VERSION 5.8 ;
BUSBITCHARS "[]" ;
DIVIDERCHAR "/" ;
UNITS
    DATABASE MICRONS 1000 ;
END UNITS

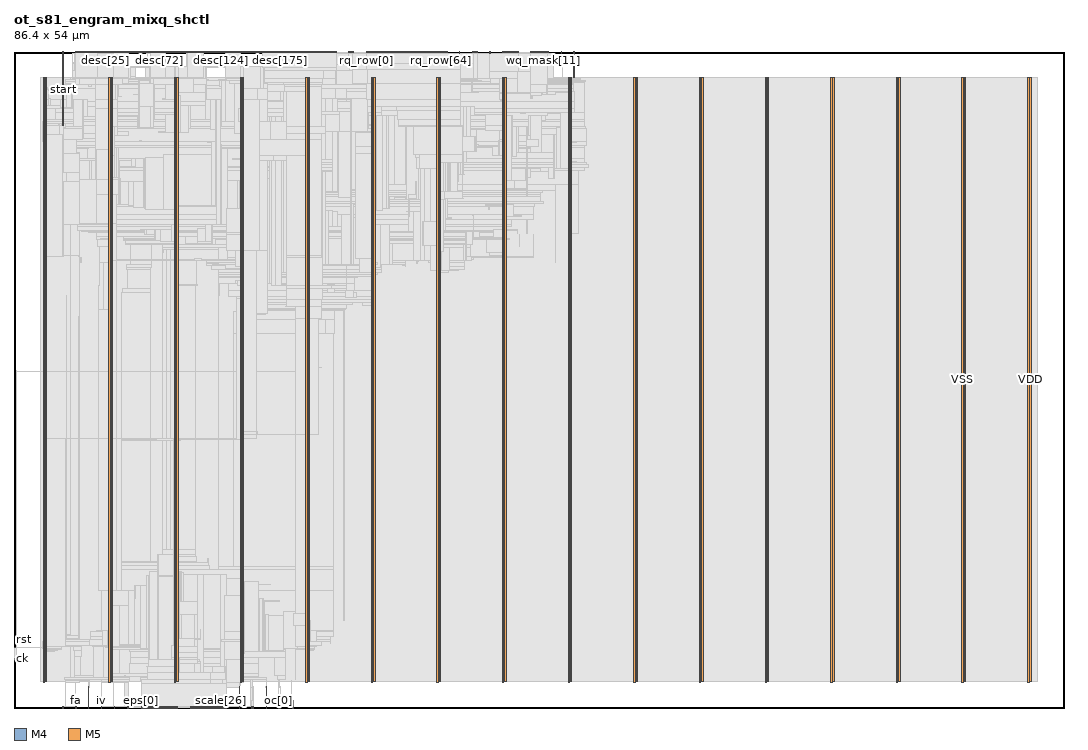
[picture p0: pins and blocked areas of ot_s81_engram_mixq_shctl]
MACRO ot_s81_engram_mixq_shctl
  FOREIGN ot_s81_engram_mixq_shctl 0 0 ;
  CLASS BLOCK ;
  SIZE 86.4 BY 54 ;
  PIN ck
    DIRECTION INPUT ;
    USE SIGNAL ;
    PORT
      LAYER M4 ;
        RECT  0 4.032 0.084 4.056 ;
    END
  END ck
  PIN copy[0]
    DIRECTION OUTPUT ;
    USE SIGNAL ;
    PORT
      LAYER M5 ;
        RECT  9.312 0 9.336 0.084 ;
    END
  END copy[0]
  PIN copy[1]
    DIRECTION OUTPUT ;
    USE SIGNAL ;
    PORT
      LAYER M5 ;
        RECT  9.408 0 9.432 0.084 ;
    END
  END copy[1]
  PIN desc[0]
    DIRECTION INPUT ;
    USE SIGNAL ;
    PORT
      LAYER M5 ;
        RECT  5.088 53.916 5.112 54 ;
    END
  END desc[0]
  PIN desc[100]
    DIRECTION INPUT ;
    USE SIGNAL ;
    PORT
      LAYER M5 ;
        RECT  14.688 53.916 14.712 54 ;
    END
  END desc[100]
  PIN desc[101]
    DIRECTION INPUT ;
    USE SIGNAL ;
    PORT
      LAYER M5 ;
        RECT  14.784 53.916 14.808 54 ;
    END
  END desc[101]
  PIN desc[102]
    DIRECTION INPUT ;
    USE SIGNAL ;
    PORT
      LAYER M5 ;
        RECT  14.88 53.916 14.904 54 ;
    END
  END desc[102]
  PIN desc[103]
    DIRECTION INPUT ;
    USE SIGNAL ;
    PORT
      LAYER M5 ;
        RECT  14.976 53.916 15 54 ;
    END
  END desc[103]
  PIN desc[104]
    DIRECTION INPUT ;
    USE SIGNAL ;
    PORT
      LAYER M5 ;
        RECT  15.072 53.916 15.096 54 ;
    END
  END desc[104]
  PIN desc[105]
    DIRECTION INPUT ;
    USE SIGNAL ;
    PORT
      LAYER M5 ;
        RECT  15.168 53.916 15.192 54 ;
    END
  END desc[105]
  PIN desc[106]
    DIRECTION INPUT ;
    USE SIGNAL ;
    PORT
      LAYER M5 ;
        RECT  15.264 53.916 15.288 54 ;
    END
  END desc[106]
  PIN desc[107]
    DIRECTION INPUT ;
    USE SIGNAL ;
    PORT
      LAYER M5 ;
        RECT  15.36 53.916 15.384 54 ;
    END
  END desc[107]
  PIN desc[108]
    DIRECTION INPUT ;
    USE SIGNAL ;
    PORT
      LAYER M5 ;
        RECT  15.456 53.916 15.48 54 ;
    END
  END desc[108]
  PIN desc[109]
    DIRECTION INPUT ;
    USE SIGNAL ;
    PORT
      LAYER M5 ;
        RECT  15.552 53.916 15.576 54 ;
    END
  END desc[109]
  PIN desc[10]
    DIRECTION INPUT ;
    USE SIGNAL ;
    PORT
      LAYER M5 ;
        RECT  6.048 53.916 6.072 54 ;
    END
  END desc[10]
  PIN desc[110]
    DIRECTION INPUT ;
    USE SIGNAL ;
    PORT
      LAYER M5 ;
        RECT  15.648 53.916 15.672 54 ;
    END
  END desc[110]
  PIN desc[111]
    DIRECTION INPUT ;
    USE SIGNAL ;
    PORT
      LAYER M5 ;
        RECT  15.744 53.916 15.768 54 ;
    END
  END desc[111]
  PIN desc[112]
    DIRECTION INPUT ;
    USE SIGNAL ;
    PORT
      LAYER M5 ;
        RECT  15.84 53.916 15.864 54 ;
    END
  END desc[112]
  PIN desc[113]
    DIRECTION INPUT ;
    USE SIGNAL ;
    PORT
      LAYER M5 ;
        RECT  15.936 53.916 15.96 54 ;
    END
  END desc[113]
  PIN desc[114]
    DIRECTION INPUT ;
    USE SIGNAL ;
    PORT
      LAYER M5 ;
        RECT  16.032 53.916 16.056 54 ;
    END
  END desc[114]
  PIN desc[115]
    DIRECTION INPUT ;
    USE SIGNAL ;
    PORT
      LAYER M5 ;
        RECT  16.128 53.916 16.152 54 ;
    END
  END desc[115]
  PIN desc[116]
    DIRECTION INPUT ;
    USE SIGNAL ;
    PORT
      LAYER M5 ;
        RECT  16.224 53.916 16.248 54 ;
    END
  END desc[116]
  PIN desc[117]
    DIRECTION INPUT ;
    USE SIGNAL ;
    PORT
      LAYER M5 ;
        RECT  16.32 53.916 16.344 54 ;
    END
  END desc[117]
  PIN desc[118]
    DIRECTION INPUT ;
    USE SIGNAL ;
    PORT
      LAYER M5 ;
        RECT  16.416 53.916 16.44 54 ;
    END
  END desc[118]
  PIN desc[119]
    DIRECTION INPUT ;
    USE SIGNAL ;
    PORT
      LAYER M5 ;
        RECT  16.512 53.916 16.536 54 ;
    END
  END desc[119]
  PIN desc[11]
    DIRECTION INPUT ;
    USE SIGNAL ;
    PORT
      LAYER M5 ;
        RECT  6.144 53.916 6.168 54 ;
    END
  END desc[11]
  PIN desc[120]
    DIRECTION INPUT ;
    USE SIGNAL ;
    PORT
      LAYER M5 ;
        RECT  16.608 53.916 16.632 54 ;
    END
  END desc[120]
  PIN desc[121]
    DIRECTION INPUT ;
    USE SIGNAL ;
    PORT
      LAYER M5 ;
        RECT  16.704 53.916 16.728 54 ;
    END
  END desc[121]
  PIN desc[122]
    DIRECTION INPUT ;
    USE SIGNAL ;
    PORT
      LAYER M5 ;
        RECT  16.8 53.916 16.824 54 ;
    END
  END desc[122]
  PIN desc[123]
    DIRECTION INPUT ;
    USE SIGNAL ;
    PORT
      LAYER M5 ;
        RECT  16.896 53.916 16.92 54 ;
    END
  END desc[123]
  PIN desc[124]
    DIRECTION INPUT ;
    USE SIGNAL ;
    PORT
      LAYER M5 ;
        RECT  16.992 53.916 17.016 54 ;
    END
  END desc[124]
  PIN desc[125]
    DIRECTION INPUT ;
    USE SIGNAL ;
    PORT
      LAYER M5 ;
        RECT  17.088 53.916 17.112 54 ;
    END
  END desc[125]
  PIN desc[126]
    DIRECTION INPUT ;
    USE SIGNAL ;
    PORT
      LAYER M5 ;
        RECT  17.184 53.916 17.208 54 ;
    END
  END desc[126]
  PIN desc[127]
    DIRECTION INPUT ;
    USE SIGNAL ;
    PORT
      LAYER M5 ;
        RECT  17.28 53.916 17.304 54 ;
    END
  END desc[127]
  PIN desc[128]
    DIRECTION INPUT ;
    USE SIGNAL ;
    PORT
      LAYER M5 ;
        RECT  17.376 53.916 17.4 54 ;
    END
  END desc[128]
  PIN desc[129]
    DIRECTION INPUT ;
    USE SIGNAL ;
    PORT
      LAYER M5 ;
        RECT  17.472 53.916 17.496 54 ;
    END
  END desc[129]
  PIN desc[12]
    DIRECTION INPUT ;
    USE SIGNAL ;
    PORT
      LAYER M5 ;
        RECT  6.24 53.916 6.264 54 ;
    END
  END desc[12]
  PIN desc[130]
    DIRECTION INPUT ;
    USE SIGNAL ;
    PORT
      LAYER M5 ;
        RECT  17.568 53.916 17.592 54 ;
    END
  END desc[130]
  PIN desc[131]
    DIRECTION INPUT ;
    USE SIGNAL ;
    PORT
      LAYER M5 ;
        RECT  17.664 53.916 17.688 54 ;
    END
  END desc[131]
  PIN desc[132]
    DIRECTION INPUT ;
    USE SIGNAL ;
    PORT
      LAYER M5 ;
        RECT  17.76 53.916 17.784 54 ;
    END
  END desc[132]
  PIN desc[133]
    DIRECTION INPUT ;
    USE SIGNAL ;
    PORT
      LAYER M5 ;
        RECT  17.856 53.916 17.88 54 ;
    END
  END desc[133]
  PIN desc[134]
    DIRECTION INPUT ;
    USE SIGNAL ;
    PORT
      LAYER M5 ;
        RECT  17.952 53.916 17.976 54 ;
    END
  END desc[134]
  PIN desc[135]
    DIRECTION INPUT ;
    USE SIGNAL ;
    PORT
      LAYER M5 ;
        RECT  18.048 53.916 18.072 54 ;
    END
  END desc[135]
  PIN desc[136]
    DIRECTION INPUT ;
    USE SIGNAL ;
    PORT
      LAYER M5 ;
        RECT  18.144 53.916 18.168 54 ;
    END
  END desc[136]
  PIN desc[137]
    DIRECTION INPUT ;
    USE SIGNAL ;
    PORT
      LAYER M5 ;
        RECT  18.24 53.916 18.264 54 ;
    END
  END desc[137]
  PIN desc[138]
    DIRECTION INPUT ;
    USE SIGNAL ;
    PORT
      LAYER M5 ;
        RECT  18.336 53.916 18.36 54 ;
    END
  END desc[138]
  PIN desc[139]
    DIRECTION INPUT ;
    USE SIGNAL ;
    PORT
      LAYER M5 ;
        RECT  18.432 53.916 18.456 54 ;
    END
  END desc[139]
  PIN desc[13]
    DIRECTION INPUT ;
    USE SIGNAL ;
    PORT
      LAYER M5 ;
        RECT  6.336 53.916 6.36 54 ;
    END
  END desc[13]
  PIN desc[140]
    DIRECTION INPUT ;
    USE SIGNAL ;
    PORT
      LAYER M5 ;
        RECT  18.528 53.916 18.552 54 ;
    END
  END desc[140]
  PIN desc[141]
    DIRECTION INPUT ;
    USE SIGNAL ;
    PORT
      LAYER M5 ;
        RECT  18.624 53.916 18.648 54 ;
    END
  END desc[141]
  PIN desc[142]
    DIRECTION INPUT ;
    USE SIGNAL ;
    PORT
      LAYER M5 ;
        RECT  18.72 53.916 18.744 54 ;
    END
  END desc[142]
  PIN desc[143]
    DIRECTION INPUT ;
    USE SIGNAL ;
    PORT
      LAYER M5 ;
        RECT  18.816 53.916 18.84 54 ;
    END
  END desc[143]
  PIN desc[144]
    DIRECTION INPUT ;
    USE SIGNAL ;
    PORT
      LAYER M5 ;
        RECT  18.912 53.916 18.936 54 ;
    END
  END desc[144]
  PIN desc[145]
    DIRECTION INPUT ;
    USE SIGNAL ;
    PORT
      LAYER M5 ;
        RECT  19.008 53.916 19.032 54 ;
    END
  END desc[145]
  PIN desc[146]
    DIRECTION INPUT ;
    USE SIGNAL ;
    PORT
      LAYER M5 ;
        RECT  19.104 53.916 19.128 54 ;
    END
  END desc[146]
  PIN desc[147]
    DIRECTION INPUT ;
    USE SIGNAL ;
    PORT
      LAYER M5 ;
        RECT  19.2 53.916 19.224 54 ;
    END
  END desc[147]
  PIN desc[148]
    DIRECTION INPUT ;
    USE SIGNAL ;
    PORT
      LAYER M5 ;
        RECT  19.296 53.916 19.32 54 ;
    END
  END desc[148]
  PIN desc[149]
    DIRECTION INPUT ;
    USE SIGNAL ;
    PORT
      LAYER M5 ;
        RECT  19.392 53.916 19.416 54 ;
    END
  END desc[149]
  PIN desc[14]
    DIRECTION INPUT ;
    USE SIGNAL ;
    PORT
      LAYER M5 ;
        RECT  6.432 53.916 6.456 54 ;
    END
  END desc[14]
  PIN desc[150]
    DIRECTION INPUT ;
    USE SIGNAL ;
    PORT
      LAYER M5 ;
        RECT  19.488 53.916 19.512 54 ;
    END
  END desc[150]
  PIN desc[151]
    DIRECTION INPUT ;
    USE SIGNAL ;
    PORT
      LAYER M5 ;
        RECT  19.584 53.916 19.608 54 ;
    END
  END desc[151]
  PIN desc[152]
    DIRECTION INPUT ;
    USE SIGNAL ;
    PORT
      LAYER M5 ;
        RECT  19.68 53.916 19.704 54 ;
    END
  END desc[152]
  PIN desc[153]
    DIRECTION INPUT ;
    USE SIGNAL ;
    PORT
      LAYER M5 ;
        RECT  19.776 53.916 19.8 54 ;
    END
  END desc[153]
  PIN desc[154]
    DIRECTION INPUT ;
    USE SIGNAL ;
    PORT
      LAYER M5 ;
        RECT  19.872 53.916 19.896 54 ;
    END
  END desc[154]
  PIN desc[155]
    DIRECTION INPUT ;
    USE SIGNAL ;
    PORT
      LAYER M5 ;
        RECT  19.968 53.916 19.992 54 ;
    END
  END desc[155]
  PIN desc[156]
    DIRECTION INPUT ;
    USE SIGNAL ;
    PORT
      LAYER M5 ;
        RECT  20.064 53.916 20.088 54 ;
    END
  END desc[156]
  PIN desc[157]
    DIRECTION INPUT ;
    USE SIGNAL ;
    PORT
      LAYER M5 ;
        RECT  20.16 53.916 20.184 54 ;
    END
  END desc[157]
  PIN desc[158]
    DIRECTION INPUT ;
    USE SIGNAL ;
    PORT
      LAYER M5 ;
        RECT  20.256 53.916 20.28 54 ;
    END
  END desc[158]
  PIN desc[159]
    DIRECTION INPUT ;
    USE SIGNAL ;
    PORT
      LAYER M5 ;
        RECT  20.352 53.916 20.376 54 ;
    END
  END desc[159]
  PIN desc[15]
    DIRECTION INPUT ;
    USE SIGNAL ;
    PORT
      LAYER M5 ;
        RECT  6.528 53.916 6.552 54 ;
    END
  END desc[15]
  PIN desc[160]
    DIRECTION INPUT ;
    USE SIGNAL ;
    PORT
      LAYER M5 ;
        RECT  20.448 53.916 20.472 54 ;
    END
  END desc[160]
  PIN desc[161]
    DIRECTION INPUT ;
    USE SIGNAL ;
    PORT
      LAYER M5 ;
        RECT  20.544 53.916 20.568 54 ;
    END
  END desc[161]
  PIN desc[162]
    DIRECTION INPUT ;
    USE SIGNAL ;
    PORT
      LAYER M5 ;
        RECT  20.64 53.916 20.664 54 ;
    END
  END desc[162]
  PIN desc[163]
    DIRECTION INPUT ;
    USE SIGNAL ;
    PORT
      LAYER M5 ;
        RECT  20.736 53.916 20.76 54 ;
    END
  END desc[163]
  PIN desc[164]
    DIRECTION INPUT ;
    USE SIGNAL ;
    PORT
      LAYER M5 ;
        RECT  20.832 53.916 20.856 54 ;
    END
  END desc[164]
  PIN desc[165]
    DIRECTION INPUT ;
    USE SIGNAL ;
    PORT
      LAYER M5 ;
        RECT  20.928 53.916 20.952 54 ;
    END
  END desc[165]
  PIN desc[166]
    DIRECTION INPUT ;
    USE SIGNAL ;
    PORT
      LAYER M5 ;
        RECT  21.024 53.916 21.048 54 ;
    END
  END desc[166]
  PIN desc[167]
    DIRECTION INPUT ;
    USE SIGNAL ;
    PORT
      LAYER M5 ;
        RECT  21.12 53.916 21.144 54 ;
    END
  END desc[167]
  PIN desc[168]
    DIRECTION INPUT ;
    USE SIGNAL ;
    PORT
      LAYER M5 ;
        RECT  21.216 53.916 21.24 54 ;
    END
  END desc[168]
  PIN desc[169]
    DIRECTION INPUT ;
    USE SIGNAL ;
    PORT
      LAYER M5 ;
        RECT  21.312 53.916 21.336 54 ;
    END
  END desc[169]
  PIN desc[16]
    DIRECTION INPUT ;
    USE SIGNAL ;
    PORT
      LAYER M5 ;
        RECT  6.624 53.916 6.648 54 ;
    END
  END desc[16]
  PIN desc[170]
    DIRECTION INPUT ;
    USE SIGNAL ;
    PORT
      LAYER M5 ;
        RECT  21.408 53.916 21.432 54 ;
    END
  END desc[170]
  PIN desc[171]
    DIRECTION INPUT ;
    USE SIGNAL ;
    PORT
      LAYER M5 ;
        RECT  21.504 53.916 21.528 54 ;
    END
  END desc[171]
  PIN desc[172]
    DIRECTION INPUT ;
    USE SIGNAL ;
    PORT
      LAYER M5 ;
        RECT  21.6 53.916 21.624 54 ;
    END
  END desc[172]
  PIN desc[173]
    DIRECTION INPUT ;
    USE SIGNAL ;
    PORT
      LAYER M5 ;
        RECT  21.696 53.916 21.72 54 ;
    END
  END desc[173]
  PIN desc[174]
    DIRECTION INPUT ;
    USE SIGNAL ;
    PORT
      LAYER M5 ;
        RECT  21.792 53.916 21.816 54 ;
    END
  END desc[174]
  PIN desc[175]
    DIRECTION INPUT ;
    USE SIGNAL ;
    PORT
      LAYER M5 ;
        RECT  21.888 53.916 21.912 54 ;
    END
  END desc[175]
  PIN desc[176]
    DIRECTION INPUT ;
    USE SIGNAL ;
    PORT
      LAYER M5 ;
        RECT  21.984 53.916 22.008 54 ;
    END
  END desc[176]
  PIN desc[177]
    DIRECTION INPUT ;
    USE SIGNAL ;
    PORT
      LAYER M5 ;
        RECT  22.08 53.916 22.104 54 ;
    END
  END desc[177]
  PIN desc[178]
    DIRECTION INPUT ;
    USE SIGNAL ;
    PORT
      LAYER M5 ;
        RECT  22.176 53.916 22.2 54 ;
    END
  END desc[178]
  PIN desc[179]
    DIRECTION INPUT ;
    USE SIGNAL ;
    PORT
      LAYER M5 ;
        RECT  22.272 53.916 22.296 54 ;
    END
  END desc[179]
  PIN desc[17]
    DIRECTION INPUT ;
    USE SIGNAL ;
    PORT
      LAYER M5 ;
        RECT  6.72 53.916 6.744 54 ;
    END
  END desc[17]
  PIN desc[180]
    DIRECTION INPUT ;
    USE SIGNAL ;
    PORT
      LAYER M5 ;
        RECT  22.368 53.916 22.392 54 ;
    END
  END desc[180]
  PIN desc[181]
    DIRECTION INPUT ;
    USE SIGNAL ;
    PORT
      LAYER M5 ;
        RECT  22.464 53.916 22.488 54 ;
    END
  END desc[181]
  PIN desc[182]
    DIRECTION INPUT ;
    USE SIGNAL ;
    PORT
      LAYER M5 ;
        RECT  22.56 53.916 22.584 54 ;
    END
  END desc[182]
  PIN desc[183]
    DIRECTION INPUT ;
    USE SIGNAL ;
    PORT
      LAYER M5 ;
        RECT  22.656 53.916 22.68 54 ;
    END
  END desc[183]
  PIN desc[184]
    DIRECTION INPUT ;
    USE SIGNAL ;
    PORT
      LAYER M5 ;
        RECT  22.752 53.916 22.776 54 ;
    END
  END desc[184]
  PIN desc[185]
    DIRECTION INPUT ;
    USE SIGNAL ;
    PORT
      LAYER M5 ;
        RECT  22.848 53.916 22.872 54 ;
    END
  END desc[185]
  PIN desc[186]
    DIRECTION INPUT ;
    USE SIGNAL ;
    PORT
      LAYER M5 ;
        RECT  22.944 53.916 22.968 54 ;
    END
  END desc[186]
  PIN desc[187]
    DIRECTION INPUT ;
    USE SIGNAL ;
    PORT
      LAYER M5 ;
        RECT  23.04 53.916 23.064 54 ;
    END
  END desc[187]
  PIN desc[188]
    DIRECTION INPUT ;
    USE SIGNAL ;
    PORT
      LAYER M5 ;
        RECT  23.136 53.916 23.16 54 ;
    END
  END desc[188]
  PIN desc[189]
    DIRECTION INPUT ;
    USE SIGNAL ;
    PORT
      LAYER M5 ;
        RECT  23.232 53.916 23.256 54 ;
    END
  END desc[189]
  PIN desc[18]
    DIRECTION INPUT ;
    USE SIGNAL ;
    PORT
      LAYER M5 ;
        RECT  6.816 53.916 6.84 54 ;
    END
  END desc[18]
  PIN desc[190]
    DIRECTION INPUT ;
    USE SIGNAL ;
    PORT
      LAYER M5 ;
        RECT  23.328 53.916 23.352 54 ;
    END
  END desc[190]
  PIN desc[191]
    DIRECTION INPUT ;
    USE SIGNAL ;
    PORT
      LAYER M5 ;
        RECT  23.424 53.916 23.448 54 ;
    END
  END desc[191]
  PIN desc[192]
    DIRECTION INPUT ;
    USE SIGNAL ;
    PORT
      LAYER M5 ;
        RECT  23.52 53.916 23.544 54 ;
    END
  END desc[192]
  PIN desc[193]
    DIRECTION INPUT ;
    USE SIGNAL ;
    PORT
      LAYER M5 ;
        RECT  23.616 53.916 23.64 54 ;
    END
  END desc[193]
  PIN desc[194]
    DIRECTION INPUT ;
    USE SIGNAL ;
    PORT
      LAYER M5 ;
        RECT  23.712 53.916 23.736 54 ;
    END
  END desc[194]
  PIN desc[195]
    DIRECTION INPUT ;
    USE SIGNAL ;
    PORT
      LAYER M5 ;
        RECT  23.808 53.916 23.832 54 ;
    END
  END desc[195]
  PIN desc[196]
    DIRECTION INPUT ;
    USE SIGNAL ;
    PORT
      LAYER M5 ;
        RECT  23.904 53.916 23.928 54 ;
    END
  END desc[196]
  PIN desc[197]
    DIRECTION INPUT ;
    USE SIGNAL ;
    PORT
      LAYER M5 ;
        RECT  24 53.916 24.024 54 ;
    END
  END desc[197]
  PIN desc[198]
    DIRECTION INPUT ;
    USE SIGNAL ;
    PORT
      LAYER M5 ;
        RECT  24.096 53.916 24.12 54 ;
    END
  END desc[198]
  PIN desc[199]
    DIRECTION INPUT ;
    USE SIGNAL ;
    PORT
      LAYER M5 ;
        RECT  24.192 53.916 24.216 54 ;
    END
  END desc[199]
  PIN desc[19]
    DIRECTION INPUT ;
    USE SIGNAL ;
    PORT
      LAYER M5 ;
        RECT  6.912 53.916 6.936 54 ;
    END
  END desc[19]
  PIN desc[1]
    DIRECTION INPUT ;
    USE SIGNAL ;
    PORT
      LAYER M5 ;
        RECT  5.184 53.916 5.208 54 ;
    END
  END desc[1]
  PIN desc[200]
    DIRECTION INPUT ;
    USE SIGNAL ;
    PORT
      LAYER M5 ;
        RECT  24.288 53.916 24.312 54 ;
    END
  END desc[200]
  PIN desc[201]
    DIRECTION INPUT ;
    USE SIGNAL ;
    PORT
      LAYER M5 ;
        RECT  24.384 53.916 24.408 54 ;
    END
  END desc[201]
  PIN desc[202]
    DIRECTION INPUT ;
    USE SIGNAL ;
    PORT
      LAYER M5 ;
        RECT  24.48 53.916 24.504 54 ;
    END
  END desc[202]
  PIN desc[203]
    DIRECTION INPUT ;
    USE SIGNAL ;
    PORT
      LAYER M5 ;
        RECT  24.576 53.916 24.6 54 ;
    END
  END desc[203]
  PIN desc[204]
    DIRECTION INPUT ;
    USE SIGNAL ;
    PORT
      LAYER M5 ;
        RECT  24.672 53.916 24.696 54 ;
    END
  END desc[204]
  PIN desc[205]
    DIRECTION INPUT ;
    USE SIGNAL ;
    PORT
      LAYER M5 ;
        RECT  24.768 53.916 24.792 54 ;
    END
  END desc[205]
  PIN desc[206]
    DIRECTION INPUT ;
    USE SIGNAL ;
    PORT
      LAYER M5 ;
        RECT  24.864 53.916 24.888 54 ;
    END
  END desc[206]
  PIN desc[207]
    DIRECTION INPUT ;
    USE SIGNAL ;
    PORT
      LAYER M5 ;
        RECT  24.96 53.916 24.984 54 ;
    END
  END desc[207]
  PIN desc[208]
    DIRECTION INPUT ;
    USE SIGNAL ;
    PORT
      LAYER M5 ;
        RECT  25.056 53.916 25.08 54 ;
    END
  END desc[208]
  PIN desc[209]
    DIRECTION INPUT ;
    USE SIGNAL ;
    PORT
      LAYER M5 ;
        RECT  25.152 53.916 25.176 54 ;
    END
  END desc[209]
  PIN desc[20]
    DIRECTION INPUT ;
    USE SIGNAL ;
    PORT
      LAYER M5 ;
        RECT  7.008 53.916 7.032 54 ;
    END
  END desc[20]
  PIN desc[210]
    DIRECTION INPUT ;
    USE SIGNAL ;
    PORT
      LAYER M5 ;
        RECT  25.248 53.916 25.272 54 ;
    END
  END desc[210]
  PIN desc[211]
    DIRECTION INPUT ;
    USE SIGNAL ;
    PORT
      LAYER M5 ;
        RECT  25.344 53.916 25.368 54 ;
    END
  END desc[211]
  PIN desc[212]
    DIRECTION INPUT ;
    USE SIGNAL ;
    PORT
      LAYER M5 ;
        RECT  25.44 53.916 25.464 54 ;
    END
  END desc[212]
  PIN desc[213]
    DIRECTION INPUT ;
    USE SIGNAL ;
    PORT
      LAYER M5 ;
        RECT  25.536 53.916 25.56 54 ;
    END
  END desc[213]
  PIN desc[214]
    DIRECTION INPUT ;
    USE SIGNAL ;
    PORT
      LAYER M5 ;
        RECT  25.632 53.916 25.656 54 ;
    END
  END desc[214]
  PIN desc[215]
    DIRECTION INPUT ;
    USE SIGNAL ;
    PORT
      LAYER M5 ;
        RECT  25.728 53.916 25.752 54 ;
    END
  END desc[215]
  PIN desc[216]
    DIRECTION INPUT ;
    USE SIGNAL ;
    PORT
      LAYER M5 ;
        RECT  25.824 53.916 25.848 54 ;
    END
  END desc[216]
  PIN desc[217]
    DIRECTION INPUT ;
    USE SIGNAL ;
    PORT
      LAYER M5 ;
        RECT  25.92 53.916 25.944 54 ;
    END
  END desc[217]
  PIN desc[218]
    DIRECTION INPUT ;
    USE SIGNAL ;
    PORT
      LAYER M5 ;
        RECT  26.016 53.916 26.04 54 ;
    END
  END desc[218]
  PIN desc[219]
    DIRECTION INPUT ;
    USE SIGNAL ;
    PORT
      LAYER M5 ;
        RECT  26.112 53.916 26.136 54 ;
    END
  END desc[219]
  PIN desc[21]
    DIRECTION INPUT ;
    USE SIGNAL ;
    PORT
      LAYER M5 ;
        RECT  7.104 53.916 7.128 54 ;
    END
  END desc[21]
  PIN desc[220]
    DIRECTION INPUT ;
    USE SIGNAL ;
    PORT
      LAYER M5 ;
        RECT  26.208 53.916 26.232 54 ;
    END
  END desc[220]
  PIN desc[221]
    DIRECTION INPUT ;
    USE SIGNAL ;
    PORT
      LAYER M5 ;
        RECT  26.304 53.916 26.328 54 ;
    END
  END desc[221]
  PIN desc[222]
    DIRECTION INPUT ;
    USE SIGNAL ;
    PORT
      LAYER M5 ;
        RECT  26.4 53.916 26.424 54 ;
    END
  END desc[222]
  PIN desc[223]
    DIRECTION INPUT ;
    USE SIGNAL ;
    PORT
      LAYER M5 ;
        RECT  26.496 53.916 26.52 54 ;
    END
  END desc[223]
  PIN desc[22]
    DIRECTION INPUT ;
    USE SIGNAL ;
    PORT
      LAYER M5 ;
        RECT  7.2 53.916 7.224 54 ;
    END
  END desc[22]
  PIN desc[23]
    DIRECTION INPUT ;
    USE SIGNAL ;
    PORT
      LAYER M5 ;
        RECT  7.296 53.916 7.32 54 ;
    END
  END desc[23]
  PIN desc[24]
    DIRECTION INPUT ;
    USE SIGNAL ;
    PORT
      LAYER M5 ;
        RECT  7.392 53.916 7.416 54 ;
    END
  END desc[24]
  PIN desc[25]
    DIRECTION INPUT ;
    USE SIGNAL ;
    PORT
      LAYER M5 ;
        RECT  7.488 53.916 7.512 54 ;
    END
  END desc[25]
  PIN desc[26]
    DIRECTION INPUT ;
    USE SIGNAL ;
    PORT
      LAYER M5 ;
        RECT  7.584 53.916 7.608 54 ;
    END
  END desc[26]
  PIN desc[27]
    DIRECTION INPUT ;
    USE SIGNAL ;
    PORT
      LAYER M5 ;
        RECT  7.68 53.916 7.704 54 ;
    END
  END desc[27]
  PIN desc[28]
    DIRECTION INPUT ;
    USE SIGNAL ;
    PORT
      LAYER M5 ;
        RECT  7.776 53.916 7.8 54 ;
    END
  END desc[28]
  PIN desc[29]
    DIRECTION INPUT ;
    USE SIGNAL ;
    PORT
      LAYER M5 ;
        RECT  7.872 53.916 7.896 54 ;
    END
  END desc[29]
  PIN desc[2]
    DIRECTION INPUT ;
    USE SIGNAL ;
    PORT
      LAYER M5 ;
        RECT  5.28 53.916 5.304 54 ;
    END
  END desc[2]
  PIN desc[30]
    DIRECTION INPUT ;
    USE SIGNAL ;
    PORT
      LAYER M5 ;
        RECT  7.968 53.916 7.992 54 ;
    END
  END desc[30]
  PIN desc[31]
    DIRECTION INPUT ;
    USE SIGNAL ;
    PORT
      LAYER M5 ;
        RECT  8.064 53.916 8.088 54 ;
    END
  END desc[31]
  PIN desc[32]
    DIRECTION INPUT ;
    USE SIGNAL ;
    PORT
      LAYER M5 ;
        RECT  8.16 53.916 8.184 54 ;
    END
  END desc[32]
  PIN desc[33]
    DIRECTION INPUT ;
    USE SIGNAL ;
    PORT
      LAYER M5 ;
        RECT  8.256 53.916 8.28 54 ;
    END
  END desc[33]
  PIN desc[34]
    DIRECTION INPUT ;
    USE SIGNAL ;
    PORT
      LAYER M5 ;
        RECT  8.352 53.916 8.376 54 ;
    END
  END desc[34]
  PIN desc[35]
    DIRECTION INPUT ;
    USE SIGNAL ;
    PORT
      LAYER M5 ;
        RECT  8.448 53.916 8.472 54 ;
    END
  END desc[35]
  PIN desc[36]
    DIRECTION INPUT ;
    USE SIGNAL ;
    PORT
      LAYER M5 ;
        RECT  8.544 53.916 8.568 54 ;
    END
  END desc[36]
  PIN desc[37]
    DIRECTION INPUT ;
    USE SIGNAL ;
    PORT
      LAYER M5 ;
        RECT  8.64 53.916 8.664 54 ;
    END
  END desc[37]
  PIN desc[38]
    DIRECTION INPUT ;
    USE SIGNAL ;
    PORT
      LAYER M5 ;
        RECT  8.736 53.916 8.76 54 ;
    END
  END desc[38]
  PIN desc[39]
    DIRECTION INPUT ;
    USE SIGNAL ;
    PORT
      LAYER M5 ;
        RECT  8.832 53.916 8.856 54 ;
    END
  END desc[39]
  PIN desc[3]
    DIRECTION INPUT ;
    USE SIGNAL ;
    PORT
      LAYER M5 ;
        RECT  5.376 53.916 5.4 54 ;
    END
  END desc[3]
  PIN desc[40]
    DIRECTION INPUT ;
    USE SIGNAL ;
    PORT
      LAYER M5 ;
        RECT  8.928 53.916 8.952 54 ;
    END
  END desc[40]
  PIN desc[41]
    DIRECTION INPUT ;
    USE SIGNAL ;
    PORT
      LAYER M5 ;
        RECT  9.024 53.916 9.048 54 ;
    END
  END desc[41]
  PIN desc[42]
    DIRECTION INPUT ;
    USE SIGNAL ;
    PORT
      LAYER M5 ;
        RECT  9.12 53.916 9.144 54 ;
    END
  END desc[42]
  PIN desc[43]
    DIRECTION INPUT ;
    USE SIGNAL ;
    PORT
      LAYER M5 ;
        RECT  9.216 53.916 9.24 54 ;
    END
  END desc[43]
  PIN desc[44]
    DIRECTION INPUT ;
    USE SIGNAL ;
    PORT
      LAYER M5 ;
        RECT  9.312 53.916 9.336 54 ;
    END
  END desc[44]
  PIN desc[45]
    DIRECTION INPUT ;
    USE SIGNAL ;
    PORT
      LAYER M5 ;
        RECT  9.408 53.916 9.432 54 ;
    END
  END desc[45]
  PIN desc[46]
    DIRECTION INPUT ;
    USE SIGNAL ;
    PORT
      LAYER M5 ;
        RECT  9.504 53.916 9.528 54 ;
    END
  END desc[46]
  PIN desc[47]
    DIRECTION INPUT ;
    USE SIGNAL ;
    PORT
      LAYER M5 ;
        RECT  9.6 53.916 9.624 54 ;
    END
  END desc[47]
  PIN desc[48]
    DIRECTION INPUT ;
    USE SIGNAL ;
    PORT
      LAYER M5 ;
        RECT  9.696 53.916 9.72 54 ;
    END
  END desc[48]
  PIN desc[49]
    DIRECTION INPUT ;
    USE SIGNAL ;
    PORT
      LAYER M5 ;
        RECT  9.792 53.916 9.816 54 ;
    END
  END desc[49]
  PIN desc[4]
    DIRECTION INPUT ;
    USE SIGNAL ;
    PORT
      LAYER M5 ;
        RECT  5.472 53.916 5.496 54 ;
    END
  END desc[4]
  PIN desc[50]
    DIRECTION INPUT ;
    USE SIGNAL ;
    PORT
      LAYER M5 ;
        RECT  9.888 53.916 9.912 54 ;
    END
  END desc[50]
  PIN desc[51]
    DIRECTION INPUT ;
    USE SIGNAL ;
    PORT
      LAYER M5 ;
        RECT  9.984 53.916 10.008 54 ;
    END
  END desc[51]
  PIN desc[52]
    DIRECTION INPUT ;
    USE SIGNAL ;
    PORT
      LAYER M5 ;
        RECT  10.08 53.916 10.104 54 ;
    END
  END desc[52]
  PIN desc[53]
    DIRECTION INPUT ;
    USE SIGNAL ;
    PORT
      LAYER M5 ;
        RECT  10.176 53.916 10.2 54 ;
    END
  END desc[53]
  PIN desc[54]
    DIRECTION INPUT ;
    USE SIGNAL ;
    PORT
      LAYER M5 ;
        RECT  10.272 53.916 10.296 54 ;
    END
  END desc[54]
  PIN desc[55]
    DIRECTION INPUT ;
    USE SIGNAL ;
    PORT
      LAYER M5 ;
        RECT  10.368 53.916 10.392 54 ;
    END
  END desc[55]
  PIN desc[56]
    DIRECTION INPUT ;
    USE SIGNAL ;
    PORT
      LAYER M5 ;
        RECT  10.464 53.916 10.488 54 ;
    END
  END desc[56]
  PIN desc[57]
    DIRECTION INPUT ;
    USE SIGNAL ;
    PORT
      LAYER M5 ;
        RECT  10.56 53.916 10.584 54 ;
    END
  END desc[57]
  PIN desc[58]
    DIRECTION INPUT ;
    USE SIGNAL ;
    PORT
      LAYER M5 ;
        RECT  10.656 53.916 10.68 54 ;
    END
  END desc[58]
  PIN desc[59]
    DIRECTION INPUT ;
    USE SIGNAL ;
    PORT
      LAYER M5 ;
        RECT  10.752 53.916 10.776 54 ;
    END
  END desc[59]
  PIN desc[5]
    DIRECTION INPUT ;
    USE SIGNAL ;
    PORT
      LAYER M5 ;
        RECT  5.568 53.916 5.592 54 ;
    END
  END desc[5]
  PIN desc[60]
    DIRECTION INPUT ;
    USE SIGNAL ;
    PORT
      LAYER M5 ;
        RECT  10.848 53.916 10.872 54 ;
    END
  END desc[60]
  PIN desc[61]
    DIRECTION INPUT ;
    USE SIGNAL ;
    PORT
      LAYER M5 ;
        RECT  10.944 53.916 10.968 54 ;
    END
  END desc[61]
  PIN desc[62]
    DIRECTION INPUT ;
    USE SIGNAL ;
    PORT
      LAYER M5 ;
        RECT  11.04 53.916 11.064 54 ;
    END
  END desc[62]
  PIN desc[63]
    DIRECTION INPUT ;
    USE SIGNAL ;
    PORT
      LAYER M5 ;
        RECT  11.136 53.916 11.16 54 ;
    END
  END desc[63]
  PIN desc[64]
    DIRECTION INPUT ;
    USE SIGNAL ;
    PORT
      LAYER M5 ;
        RECT  11.232 53.916 11.256 54 ;
    END
  END desc[64]
  PIN desc[65]
    DIRECTION INPUT ;
    USE SIGNAL ;
    PORT
      LAYER M5 ;
        RECT  11.328 53.916 11.352 54 ;
    END
  END desc[65]
  PIN desc[66]
    DIRECTION INPUT ;
    USE SIGNAL ;
    PORT
      LAYER M5 ;
        RECT  11.424 53.916 11.448 54 ;
    END
  END desc[66]
  PIN desc[67]
    DIRECTION INPUT ;
    USE SIGNAL ;
    PORT
      LAYER M5 ;
        RECT  11.52 53.916 11.544 54 ;
    END
  END desc[67]
  PIN desc[68]
    DIRECTION INPUT ;
    USE SIGNAL ;
    PORT
      LAYER M5 ;
        RECT  11.616 53.916 11.64 54 ;
    END
  END desc[68]
  PIN desc[69]
    DIRECTION INPUT ;
    USE SIGNAL ;
    PORT
      LAYER M5 ;
        RECT  11.712 53.916 11.736 54 ;
    END
  END desc[69]
  PIN desc[6]
    DIRECTION INPUT ;
    USE SIGNAL ;
    PORT
      LAYER M5 ;
        RECT  5.664 53.916 5.688 54 ;
    END
  END desc[6]
  PIN desc[70]
    DIRECTION INPUT ;
    USE SIGNAL ;
    PORT
      LAYER M5 ;
        RECT  11.808 53.916 11.832 54 ;
    END
  END desc[70]
  PIN desc[71]
    DIRECTION INPUT ;
    USE SIGNAL ;
    PORT
      LAYER M5 ;
        RECT  11.904 53.916 11.928 54 ;
    END
  END desc[71]
  PIN desc[72]
    DIRECTION INPUT ;
    USE SIGNAL ;
    PORT
      LAYER M5 ;
        RECT  12 53.916 12.024 54 ;
    END
  END desc[72]
  PIN desc[73]
    DIRECTION INPUT ;
    USE SIGNAL ;
    PORT
      LAYER M5 ;
        RECT  12.096 53.916 12.12 54 ;
    END
  END desc[73]
  PIN desc[74]
    DIRECTION INPUT ;
    USE SIGNAL ;
    PORT
      LAYER M5 ;
        RECT  12.192 53.916 12.216 54 ;
    END
  END desc[74]
  PIN desc[75]
    DIRECTION INPUT ;
    USE SIGNAL ;
    PORT
      LAYER M5 ;
        RECT  12.288 53.916 12.312 54 ;
    END
  END desc[75]
  PIN desc[76]
    DIRECTION INPUT ;
    USE SIGNAL ;
    PORT
      LAYER M5 ;
        RECT  12.384 53.916 12.408 54 ;
    END
  END desc[76]
  PIN desc[77]
    DIRECTION INPUT ;
    USE SIGNAL ;
    PORT
      LAYER M5 ;
        RECT  12.48 53.916 12.504 54 ;
    END
  END desc[77]
  PIN desc[78]
    DIRECTION INPUT ;
    USE SIGNAL ;
    PORT
      LAYER M5 ;
        RECT  12.576 53.916 12.6 54 ;
    END
  END desc[78]
  PIN desc[79]
    DIRECTION INPUT ;
    USE SIGNAL ;
    PORT
      LAYER M5 ;
        RECT  12.672 53.916 12.696 54 ;
    END
  END desc[79]
  PIN desc[7]
    DIRECTION INPUT ;
    USE SIGNAL ;
    PORT
      LAYER M5 ;
        RECT  5.76 53.916 5.784 54 ;
    END
  END desc[7]
  PIN desc[80]
    DIRECTION INPUT ;
    USE SIGNAL ;
    PORT
      LAYER M5 ;
        RECT  12.768 53.916 12.792 54 ;
    END
  END desc[80]
  PIN desc[81]
    DIRECTION INPUT ;
    USE SIGNAL ;
    PORT
      LAYER M5 ;
        RECT  12.864 53.916 12.888 54 ;
    END
  END desc[81]
  PIN desc[82]
    DIRECTION INPUT ;
    USE SIGNAL ;
    PORT
      LAYER M5 ;
        RECT  12.96 53.916 12.984 54 ;
    END
  END desc[82]
  PIN desc[83]
    DIRECTION INPUT ;
    USE SIGNAL ;
    PORT
      LAYER M5 ;
        RECT  13.056 53.916 13.08 54 ;
    END
  END desc[83]
  PIN desc[84]
    DIRECTION INPUT ;
    USE SIGNAL ;
    PORT
      LAYER M5 ;
        RECT  13.152 53.916 13.176 54 ;
    END
  END desc[84]
  PIN desc[85]
    DIRECTION INPUT ;
    USE SIGNAL ;
    PORT
      LAYER M5 ;
        RECT  13.248 53.916 13.272 54 ;
    END
  END desc[85]
  PIN desc[86]
    DIRECTION INPUT ;
    USE SIGNAL ;
    PORT
      LAYER M5 ;
        RECT  13.344 53.916 13.368 54 ;
    END
  END desc[86]
  PIN desc[87]
    DIRECTION INPUT ;
    USE SIGNAL ;
    PORT
      LAYER M5 ;
        RECT  13.44 53.916 13.464 54 ;
    END
  END desc[87]
  PIN desc[88]
    DIRECTION INPUT ;
    USE SIGNAL ;
    PORT
      LAYER M5 ;
        RECT  13.536 53.916 13.56 54 ;
    END
  END desc[88]
  PIN desc[89]
    DIRECTION INPUT ;
    USE SIGNAL ;
    PORT
      LAYER M5 ;
        RECT  13.632 53.916 13.656 54 ;
    END
  END desc[89]
  PIN desc[8]
    DIRECTION INPUT ;
    USE SIGNAL ;
    PORT
      LAYER M5 ;
        RECT  5.856 53.916 5.88 54 ;
    END
  END desc[8]
  PIN desc[90]
    DIRECTION INPUT ;
    USE SIGNAL ;
    PORT
      LAYER M5 ;
        RECT  13.728 53.916 13.752 54 ;
    END
  END desc[90]
  PIN desc[91]
    DIRECTION INPUT ;
    USE SIGNAL ;
    PORT
      LAYER M5 ;
        RECT  13.824 53.916 13.848 54 ;
    END
  END desc[91]
  PIN desc[92]
    DIRECTION INPUT ;
    USE SIGNAL ;
    PORT
      LAYER M5 ;
        RECT  13.92 53.916 13.944 54 ;
    END
  END desc[92]
  PIN desc[93]
    DIRECTION INPUT ;
    USE SIGNAL ;
    PORT
      LAYER M5 ;
        RECT  14.016 53.916 14.04 54 ;
    END
  END desc[93]
  PIN desc[94]
    DIRECTION INPUT ;
    USE SIGNAL ;
    PORT
      LAYER M5 ;
        RECT  14.112 53.916 14.136 54 ;
    END
  END desc[94]
  PIN desc[95]
    DIRECTION INPUT ;
    USE SIGNAL ;
    PORT
      LAYER M5 ;
        RECT  14.208 53.916 14.232 54 ;
    END
  END desc[95]
  PIN desc[96]
    DIRECTION INPUT ;
    USE SIGNAL ;
    PORT
      LAYER M5 ;
        RECT  14.304 53.916 14.328 54 ;
    END
  END desc[96]
  PIN desc[97]
    DIRECTION INPUT ;
    USE SIGNAL ;
    PORT
      LAYER M5 ;
        RECT  14.4 53.916 14.424 54 ;
    END
  END desc[97]
  PIN desc[98]
    DIRECTION INPUT ;
    USE SIGNAL ;
    PORT
      LAYER M5 ;
        RECT  14.496 53.916 14.52 54 ;
    END
  END desc[98]
  PIN desc[99]
    DIRECTION INPUT ;
    USE SIGNAL ;
    PORT
      LAYER M5 ;
        RECT  14.592 53.916 14.616 54 ;
    END
  END desc[99]
  PIN desc[9]
    DIRECTION INPUT ;
    USE SIGNAL ;
    PORT
      LAYER M5 ;
        RECT  5.952 53.916 5.976 54 ;
    END
  END desc[9]
  PIN done
    DIRECTION OUTPUT ;
    USE SIGNAL ;
    PORT
      LAYER M5 ;
        RECT  45.024 53.916 45.048 54 ;
    END
    PORT
      LAYER M5 ;
        RECT  45.024 52.981 45.048 53.968 ;
    END
  END done
  PIN eps[0]
    DIRECTION OUTPUT ;
    USE SIGNAL ;
    PORT
      LAYER M5 ;
        RECT  10.464 0 10.488 0.084 ;
    END
  END eps[0]
  PIN eps[10]
    DIRECTION OUTPUT ;
    USE SIGNAL ;
    PORT
      LAYER M5 ;
        RECT  11.424 0 11.448 0.084 ;
    END
  END eps[10]
  PIN eps[11]
    DIRECTION OUTPUT ;
    USE SIGNAL ;
    PORT
      LAYER M5 ;
        RECT  11.52 0 11.544 0.084 ;
    END
  END eps[11]
  PIN eps[12]
    DIRECTION OUTPUT ;
    USE SIGNAL ;
    PORT
      LAYER M5 ;
        RECT  11.616 0 11.64 0.084 ;
    END
  END eps[12]
  PIN eps[13]
    DIRECTION OUTPUT ;
    USE SIGNAL ;
    PORT
      LAYER M5 ;
        RECT  11.712 0 11.736 0.084 ;
    END
  END eps[13]
  PIN eps[14]
    DIRECTION OUTPUT ;
    USE SIGNAL ;
    PORT
      LAYER M5 ;
        RECT  11.808 0 11.832 0.084 ;
    END
  END eps[14]
  PIN eps[15]
    DIRECTION OUTPUT ;
    USE SIGNAL ;
    PORT
      LAYER M5 ;
        RECT  11.904 0 11.928 0.084 ;
    END
  END eps[15]
  PIN eps[16]
    DIRECTION OUTPUT ;
    USE SIGNAL ;
    PORT
      LAYER M5 ;
        RECT  12 0 12.024 0.084 ;
    END
  END eps[16]
  PIN eps[17]
    DIRECTION OUTPUT ;
    USE SIGNAL ;
    PORT
      LAYER M5 ;
        RECT  12.096 0 12.12 0.084 ;
    END
  END eps[17]
  PIN eps[18]
    DIRECTION OUTPUT ;
    USE SIGNAL ;
    PORT
      LAYER M5 ;
        RECT  12.192 0 12.216 0.084 ;
    END
  END eps[18]
  PIN eps[19]
    DIRECTION OUTPUT ;
    USE SIGNAL ;
    PORT
      LAYER M5 ;
        RECT  12.288 0 12.312 0.084 ;
    END
  END eps[19]
  PIN eps[1]
    DIRECTION OUTPUT ;
    USE SIGNAL ;
    PORT
      LAYER M5 ;
        RECT  10.56 0 10.584 0.084 ;
    END
  END eps[1]
  PIN eps[20]
    DIRECTION OUTPUT ;
    USE SIGNAL ;
    PORT
      LAYER M5 ;
        RECT  12.384 0 12.408 0.084 ;
    END
  END eps[20]
  PIN eps[21]
    DIRECTION OUTPUT ;
    USE SIGNAL ;
    PORT
      LAYER M5 ;
        RECT  12.48 0 12.504 0.084 ;
    END
  END eps[21]
  PIN eps[22]
    DIRECTION OUTPUT ;
    USE SIGNAL ;
    PORT
      LAYER M5 ;
        RECT  12.576 0 12.6 0.084 ;
    END
  END eps[22]
  PIN eps[23]
    DIRECTION OUTPUT ;
    USE SIGNAL ;
    PORT
      LAYER M5 ;
        RECT  12.672 0 12.696 0.084 ;
    END
  END eps[23]
  PIN eps[24]
    DIRECTION OUTPUT ;
    USE SIGNAL ;
    PORT
      LAYER M5 ;
        RECT  12.768 0 12.792 0.084 ;
    END
  END eps[24]
  PIN eps[25]
    DIRECTION OUTPUT ;
    USE SIGNAL ;
    PORT
      LAYER M5 ;
        RECT  12.864 0 12.888 0.084 ;
    END
  END eps[25]
  PIN eps[26]
    DIRECTION OUTPUT ;
    USE SIGNAL ;
    PORT
      LAYER M5 ;
        RECT  12.96 0 12.984 0.084 ;
    END
  END eps[26]
  PIN eps[27]
    DIRECTION OUTPUT ;
    USE SIGNAL ;
    PORT
      LAYER M5 ;
        RECT  13.056 0 13.08 0.084 ;
    END
  END eps[27]
  PIN eps[28]
    DIRECTION OUTPUT ;
    USE SIGNAL ;
    PORT
      LAYER M5 ;
        RECT  13.152 0 13.176 0.084 ;
    END
  END eps[28]
  PIN eps[29]
    DIRECTION OUTPUT ;
    USE SIGNAL ;
    PORT
      LAYER M5 ;
        RECT  13.248 0 13.272 0.084 ;
    END
  END eps[29]
  PIN eps[2]
    DIRECTION OUTPUT ;
    USE SIGNAL ;
    PORT
      LAYER M5 ;
        RECT  10.656 0 10.68 0.084 ;
    END
  END eps[2]
  PIN eps[30]
    DIRECTION OUTPUT ;
    USE SIGNAL ;
    PORT
      LAYER M5 ;
        RECT  13.344 0 13.368 0.084 ;
    END
  END eps[30]
  PIN eps[31]
    DIRECTION OUTPUT ;
    USE SIGNAL ;
    PORT
      LAYER M5 ;
        RECT  13.44 0 13.464 0.084 ;
    END
  END eps[31]
  PIN eps[3]
    DIRECTION OUTPUT ;
    USE SIGNAL ;
    PORT
      LAYER M5 ;
        RECT  10.752 0 10.776 0.084 ;
    END
  END eps[3]
  PIN eps[4]
    DIRECTION OUTPUT ;
    USE SIGNAL ;
    PORT
      LAYER M5 ;
        RECT  10.848 0 10.872 0.084 ;
    END
  END eps[4]
  PIN eps[5]
    DIRECTION OUTPUT ;
    USE SIGNAL ;
    PORT
      LAYER M5 ;
        RECT  10.944 0 10.968 0.084 ;
    END
  END eps[5]
  PIN eps[6]
    DIRECTION OUTPUT ;
    USE SIGNAL ;
    PORT
      LAYER M5 ;
        RECT  11.04 0 11.064 0.084 ;
    END
  END eps[6]
  PIN eps[7]
    DIRECTION OUTPUT ;
    USE SIGNAL ;
    PORT
      LAYER M5 ;
        RECT  11.136 0 11.16 0.084 ;
    END
  END eps[7]
  PIN eps[8]
    DIRECTION OUTPUT ;
    USE SIGNAL ;
    PORT
      LAYER M5 ;
        RECT  11.232 0 11.256 0.084 ;
    END
  END eps[8]
  PIN eps[9]
    DIRECTION OUTPUT ;
    USE SIGNAL ;
    PORT
      LAYER M5 ;
        RECT  11.328 0 11.352 0.084 ;
    END
  END eps[9]
  PIN fa
    DIRECTION OUTPUT ;
    USE SIGNAL ;
    PORT
      LAYER M5 ;
        RECT  5.088 0 5.112 0.084 ;
    END
    PORT
      LAYER M5 ;
        RECT  5.088 0.016 5.112 0.131 ;
    END
  END fa
  PIN fault
    DIRECTION OUTPUT ;
    USE SIGNAL ;
    PORT
      LAYER M5 ;
        RECT  46.08 53.916 46.104 54 ;
    END
    PORT
      LAYER M5 ;
        RECT  46.08 51.863 46.104 53.968 ;
    END
  END fault
  PIN fr
    DIRECTION OUTPUT ;
    USE SIGNAL ;
    PORT
      LAYER M5 ;
        RECT  4.032 0 4.056 0.084 ;
    END
    PORT
      LAYER M5 ;
        RECT  4.032 0.016 4.056 0.131 ;
    END
  END fr
  PIN gc[0]
    DIRECTION INPUT ;
    USE SIGNAL ;
    PORT
      LAYER M5 ;
        RECT  19.584 0 19.608 0.084 ;
    END
  END gc[0]
  PIN gc[1]
    DIRECTION INPUT ;
    USE SIGNAL ;
    PORT
      LAYER M5 ;
        RECT  19.68 0 19.704 0.084 ;
    END
  END gc[1]
  PIN go
    DIRECTION OUTPUT ;
    USE SIGNAL ;
    PORT
      LAYER M5 ;
        RECT  6.144 0 6.168 0.084 ;
    END
    PORT
      LAYER M5 ;
        RECT  6.144 0.016 6.168 1.763 ;
    END
  END go
  PIN gv
    DIRECTION INPUT ;
    USE SIGNAL ;
    PORT
      LAYER M5 ;
        RECT  18.528 0 18.552 0.084 ;
    END
    PORT
      LAYER M5 ;
        RECT  18.528 0.016 18.552 1.763 ;
    END
  END gv
  PIN iv
    DIRECTION OUTPUT ;
    USE SIGNAL ;
    PORT
      LAYER M5 ;
        RECT  7.2 0 7.224 0.084 ;
    END
    PORT
      LAYER M5 ;
        RECT  7.2 0.016 7.224 0.131 ;
    END
  END iv
  PIN mf
    DIRECTION INPUT ;
    USE SIGNAL ;
    PORT
      LAYER M5 ;
        RECT  22.944 0 22.968 0.084 ;
    END
    PORT
      LAYER M5 ;
        RECT  22.944 0.016 22.968 0.611 ;
    END
  END mf
  PIN oc[0]
    DIRECTION INPUT ;
    USE SIGNAL ;
    PORT
      LAYER M5 ;
        RECT  21.792 0 21.816 0.084 ;
    END
  END oc[0]
  PIN oc[1]
    DIRECTION INPUT ;
    USE SIGNAL ;
    PORT
      LAYER M5 ;
        RECT  21.888 0 21.912 0.084 ;
    END
  END oc[1]
  PIN ov
    DIRECTION INPUT ;
    USE SIGNAL ;
    PORT
      LAYER M5 ;
        RECT  20.736 0 20.76 0.084 ;
    END
    PORT
      LAYER M5 ;
        RECT  20.736 0.016 20.76 1.763 ;
    END
  END ov
  PIN phase
    DIRECTION OUTPUT ;
    USE SIGNAL ;
    PORT
      LAYER M5 ;
        RECT  8.256 0 8.28 0.084 ;
    END
    PORT
      LAYER M5 ;
        RECT  8.256 0.016 8.28 0.131 ;
    END
  END phase
  PIN rq_row[0]
    DIRECTION OUTPUT ;
    USE SIGNAL ;
    PORT
      LAYER M5 ;
        RECT  28.992 53.916 29.016 54 ;
    END
  END rq_row[0]
  PIN rq_row[10]
    DIRECTION OUTPUT ;
    USE SIGNAL ;
    PORT
      LAYER M5 ;
        RECT  29.952 53.916 29.976 54 ;
    END
  END rq_row[10]
  PIN rq_row[11]
    DIRECTION OUTPUT ;
    USE SIGNAL ;
    PORT
      LAYER M5 ;
        RECT  30.048 53.916 30.072 54 ;
    END
  END rq_row[11]
  PIN rq_row[12]
    DIRECTION OUTPUT ;
    USE SIGNAL ;
    PORT
      LAYER M5 ;
        RECT  30.144 53.916 30.168 54 ;
    END
  END rq_row[12]
  PIN rq_row[13]
    DIRECTION OUTPUT ;
    USE SIGNAL ;
    PORT
      LAYER M5 ;
        RECT  30.24 53.916 30.264 54 ;
    END
  END rq_row[13]
  PIN rq_row[14]
    DIRECTION OUTPUT ;
    USE SIGNAL ;
    PORT
      LAYER M5 ;
        RECT  30.336 53.916 30.36 54 ;
    END
  END rq_row[14]
  PIN rq_row[15]
    DIRECTION OUTPUT ;
    USE SIGNAL ;
    PORT
      LAYER M5 ;
        RECT  30.432 53.916 30.456 54 ;
    END
  END rq_row[15]
  PIN rq_row[16]
    DIRECTION OUTPUT ;
    USE SIGNAL ;
    PORT
      LAYER M5 ;
        RECT  30.528 53.916 30.552 54 ;
    END
  END rq_row[16]
  PIN rq_row[17]
    DIRECTION OUTPUT ;
    USE SIGNAL ;
    PORT
      LAYER M5 ;
        RECT  30.624 53.916 30.648 54 ;
    END
  END rq_row[17]
  PIN rq_row[18]
    DIRECTION OUTPUT ;
    USE SIGNAL ;
    PORT
      LAYER M5 ;
        RECT  30.72 53.916 30.744 54 ;
    END
  END rq_row[18]
  PIN rq_row[19]
    DIRECTION OUTPUT ;
    USE SIGNAL ;
    PORT
      LAYER M5 ;
        RECT  30.816 53.916 30.84 54 ;
    END
  END rq_row[19]
  PIN rq_row[1]
    DIRECTION OUTPUT ;
    USE SIGNAL ;
    PORT
      LAYER M5 ;
        RECT  29.088 53.916 29.112 54 ;
    END
  END rq_row[1]
  PIN rq_row[20]
    DIRECTION OUTPUT ;
    USE SIGNAL ;
    PORT
      LAYER M5 ;
        RECT  30.912 53.916 30.936 54 ;
    END
  END rq_row[20]
  PIN rq_row[21]
    DIRECTION OUTPUT ;
    USE SIGNAL ;
    PORT
      LAYER M5 ;
        RECT  31.008 53.916 31.032 54 ;
    END
  END rq_row[21]
  PIN rq_row[22]
    DIRECTION OUTPUT ;
    USE SIGNAL ;
    PORT
      LAYER M5 ;
        RECT  31.104 53.916 31.128 54 ;
    END
  END rq_row[22]
  PIN rq_row[23]
    DIRECTION OUTPUT ;
    USE SIGNAL ;
    PORT
      LAYER M5 ;
        RECT  31.2 53.916 31.224 54 ;
    END
  END rq_row[23]
  PIN rq_row[24]
    DIRECTION OUTPUT ;
    USE SIGNAL ;
    PORT
      LAYER M5 ;
        RECT  31.296 53.916 31.32 54 ;
    END
  END rq_row[24]
  PIN rq_row[25]
    DIRECTION OUTPUT ;
    USE SIGNAL ;
    PORT
      LAYER M5 ;
        RECT  31.392 53.916 31.416 54 ;
    END
  END rq_row[25]
  PIN rq_row[26]
    DIRECTION OUTPUT ;
    USE SIGNAL ;
    PORT
      LAYER M5 ;
        RECT  31.488 53.916 31.512 54 ;
    END
  END rq_row[26]
  PIN rq_row[27]
    DIRECTION OUTPUT ;
    USE SIGNAL ;
    PORT
      LAYER M5 ;
        RECT  31.584 53.916 31.608 54 ;
    END
  END rq_row[27]
  PIN rq_row[28]
    DIRECTION OUTPUT ;
    USE SIGNAL ;
    PORT
      LAYER M5 ;
        RECT  31.68 53.916 31.704 54 ;
    END
  END rq_row[28]
  PIN rq_row[29]
    DIRECTION OUTPUT ;
    USE SIGNAL ;
    PORT
      LAYER M5 ;
        RECT  31.776 53.916 31.8 54 ;
    END
  END rq_row[29]
  PIN rq_row[2]
    DIRECTION OUTPUT ;
    USE SIGNAL ;
    PORT
      LAYER M5 ;
        RECT  29.184 53.916 29.208 54 ;
    END
  END rq_row[2]
  PIN rq_row[30]
    DIRECTION OUTPUT ;
    USE SIGNAL ;
    PORT
      LAYER M5 ;
        RECT  31.872 53.916 31.896 54 ;
    END
  END rq_row[30]
  PIN rq_row[31]
    DIRECTION OUTPUT ;
    USE SIGNAL ;
    PORT
      LAYER M5 ;
        RECT  31.968 53.916 31.992 54 ;
    END
  END rq_row[31]
  PIN rq_row[32]
    DIRECTION OUTPUT ;
    USE SIGNAL ;
    PORT
      LAYER M5 ;
        RECT  32.064 53.916 32.088 54 ;
    END
  END rq_row[32]
  PIN rq_row[33]
    DIRECTION OUTPUT ;
    USE SIGNAL ;
    PORT
      LAYER M5 ;
        RECT  32.16 53.916 32.184 54 ;
    END
  END rq_row[33]
  PIN rq_row[34]
    DIRECTION OUTPUT ;
    USE SIGNAL ;
    PORT
      LAYER M5 ;
        RECT  32.256 53.916 32.28 54 ;
    END
  END rq_row[34]
  PIN rq_row[35]
    DIRECTION OUTPUT ;
    USE SIGNAL ;
    PORT
      LAYER M5 ;
        RECT  32.352 53.916 32.376 54 ;
    END
  END rq_row[35]
  PIN rq_row[36]
    DIRECTION OUTPUT ;
    USE SIGNAL ;
    PORT
      LAYER M5 ;
        RECT  32.448 53.916 32.472 54 ;
    END
  END rq_row[36]
  PIN rq_row[37]
    DIRECTION OUTPUT ;
    USE SIGNAL ;
    PORT
      LAYER M5 ;
        RECT  32.544 53.916 32.568 54 ;
    END
  END rq_row[37]
  PIN rq_row[38]
    DIRECTION OUTPUT ;
    USE SIGNAL ;
    PORT
      LAYER M5 ;
        RECT  32.64 53.916 32.664 54 ;
    END
  END rq_row[38]
  PIN rq_row[39]
    DIRECTION OUTPUT ;
    USE SIGNAL ;
    PORT
      LAYER M5 ;
        RECT  32.736 53.916 32.76 54 ;
    END
  END rq_row[39]
  PIN rq_row[3]
    DIRECTION OUTPUT ;
    USE SIGNAL ;
    PORT
      LAYER M5 ;
        RECT  29.28 53.916 29.304 54 ;
    END
  END rq_row[3]
  PIN rq_row[40]
    DIRECTION OUTPUT ;
    USE SIGNAL ;
    PORT
      LAYER M5 ;
        RECT  32.832 53.916 32.856 54 ;
    END
  END rq_row[40]
  PIN rq_row[41]
    DIRECTION OUTPUT ;
    USE SIGNAL ;
    PORT
      LAYER M5 ;
        RECT  32.928 53.916 32.952 54 ;
    END
  END rq_row[41]
  PIN rq_row[42]
    DIRECTION OUTPUT ;
    USE SIGNAL ;
    PORT
      LAYER M5 ;
        RECT  33.024 53.916 33.048 54 ;
    END
  END rq_row[42]
  PIN rq_row[43]
    DIRECTION OUTPUT ;
    USE SIGNAL ;
    PORT
      LAYER M5 ;
        RECT  33.12 53.916 33.144 54 ;
    END
  END rq_row[43]
  PIN rq_row[44]
    DIRECTION OUTPUT ;
    USE SIGNAL ;
    PORT
      LAYER M5 ;
        RECT  33.216 53.916 33.24 54 ;
    END
  END rq_row[44]
  PIN rq_row[45]
    DIRECTION OUTPUT ;
    USE SIGNAL ;
    PORT
      LAYER M5 ;
        RECT  33.312 53.916 33.336 54 ;
    END
  END rq_row[45]
  PIN rq_row[46]
    DIRECTION OUTPUT ;
    USE SIGNAL ;
    PORT
      LAYER M5 ;
        RECT  33.408 53.916 33.432 54 ;
    END
  END rq_row[46]
  PIN rq_row[47]
    DIRECTION OUTPUT ;
    USE SIGNAL ;
    PORT
      LAYER M5 ;
        RECT  33.504 53.916 33.528 54 ;
    END
  END rq_row[47]
  PIN rq_row[48]
    DIRECTION OUTPUT ;
    USE SIGNAL ;
    PORT
      LAYER M5 ;
        RECT  33.6 53.916 33.624 54 ;
    END
  END rq_row[48]
  PIN rq_row[49]
    DIRECTION OUTPUT ;
    USE SIGNAL ;
    PORT
      LAYER M5 ;
        RECT  33.696 53.916 33.72 54 ;
    END
  END rq_row[49]
  PIN rq_row[4]
    DIRECTION OUTPUT ;
    USE SIGNAL ;
    PORT
      LAYER M5 ;
        RECT  29.376 53.916 29.4 54 ;
    END
  END rq_row[4]
  PIN rq_row[50]
    DIRECTION OUTPUT ;
    USE SIGNAL ;
    PORT
      LAYER M5 ;
        RECT  33.792 53.916 33.816 54 ;
    END
  END rq_row[50]
  PIN rq_row[51]
    DIRECTION OUTPUT ;
    USE SIGNAL ;
    PORT
      LAYER M5 ;
        RECT  33.888 53.916 33.912 54 ;
    END
  END rq_row[51]
  PIN rq_row[52]
    DIRECTION OUTPUT ;
    USE SIGNAL ;
    PORT
      LAYER M5 ;
        RECT  33.984 53.916 34.008 54 ;
    END
  END rq_row[52]
  PIN rq_row[53]
    DIRECTION OUTPUT ;
    USE SIGNAL ;
    PORT
      LAYER M5 ;
        RECT  34.08 53.916 34.104 54 ;
    END
  END rq_row[53]
  PIN rq_row[54]
    DIRECTION OUTPUT ;
    USE SIGNAL ;
    PORT
      LAYER M5 ;
        RECT  34.176 53.916 34.2 54 ;
    END
  END rq_row[54]
  PIN rq_row[55]
    DIRECTION OUTPUT ;
    USE SIGNAL ;
    PORT
      LAYER M5 ;
        RECT  34.272 53.916 34.296 54 ;
    END
  END rq_row[55]
  PIN rq_row[56]
    DIRECTION OUTPUT ;
    USE SIGNAL ;
    PORT
      LAYER M5 ;
        RECT  34.368 53.916 34.392 54 ;
    END
  END rq_row[56]
  PIN rq_row[57]
    DIRECTION OUTPUT ;
    USE SIGNAL ;
    PORT
      LAYER M5 ;
        RECT  34.464 53.916 34.488 54 ;
    END
  END rq_row[57]
  PIN rq_row[58]
    DIRECTION OUTPUT ;
    USE SIGNAL ;
    PORT
      LAYER M5 ;
        RECT  34.56 53.916 34.584 54 ;
    END
  END rq_row[58]
  PIN rq_row[59]
    DIRECTION OUTPUT ;
    USE SIGNAL ;
    PORT
      LAYER M5 ;
        RECT  34.656 53.916 34.68 54 ;
    END
  END rq_row[59]
  PIN rq_row[5]
    DIRECTION OUTPUT ;
    USE SIGNAL ;
    PORT
      LAYER M5 ;
        RECT  29.472 53.916 29.496 54 ;
    END
  END rq_row[5]
  PIN rq_row[60]
    DIRECTION OUTPUT ;
    USE SIGNAL ;
    PORT
      LAYER M5 ;
        RECT  34.752 53.916 34.776 54 ;
    END
  END rq_row[60]
  PIN rq_row[61]
    DIRECTION OUTPUT ;
    USE SIGNAL ;
    PORT
      LAYER M5 ;
        RECT  34.848 53.916 34.872 54 ;
    END
  END rq_row[61]
  PIN rq_row[62]
    DIRECTION OUTPUT ;
    USE SIGNAL ;
    PORT
      LAYER M5 ;
        RECT  34.944 53.916 34.968 54 ;
    END
  END rq_row[62]
  PIN rq_row[63]
    DIRECTION OUTPUT ;
    USE SIGNAL ;
    PORT
      LAYER M5 ;
        RECT  35.04 53.916 35.064 54 ;
    END
  END rq_row[63]
  PIN rq_row[64]
    DIRECTION OUTPUT ;
    USE SIGNAL ;
    PORT
      LAYER M5 ;
        RECT  35.136 53.916 35.16 54 ;
    END
  END rq_row[64]
  PIN rq_row[65]
    DIRECTION OUTPUT ;
    USE SIGNAL ;
    PORT
      LAYER M5 ;
        RECT  35.232 53.916 35.256 54 ;
    END
  END rq_row[65]
  PIN rq_row[66]
    DIRECTION OUTPUT ;
    USE SIGNAL ;
    PORT
      LAYER M5 ;
        RECT  35.328 53.916 35.352 54 ;
    END
  END rq_row[66]
  PIN rq_row[67]
    DIRECTION OUTPUT ;
    USE SIGNAL ;
    PORT
      LAYER M5 ;
        RECT  35.424 53.916 35.448 54 ;
    END
  END rq_row[67]
  PIN rq_row[68]
    DIRECTION OUTPUT ;
    USE SIGNAL ;
    PORT
      LAYER M5 ;
        RECT  35.52 53.916 35.544 54 ;
    END
  END rq_row[68]
  PIN rq_row[69]
    DIRECTION OUTPUT ;
    USE SIGNAL ;
    PORT
      LAYER M5 ;
        RECT  35.616 53.916 35.64 54 ;
    END
  END rq_row[69]
  PIN rq_row[6]
    DIRECTION OUTPUT ;
    USE SIGNAL ;
    PORT
      LAYER M5 ;
        RECT  29.568 53.916 29.592 54 ;
    END
  END rq_row[6]
  PIN rq_row[7]
    DIRECTION OUTPUT ;
    USE SIGNAL ;
    PORT
      LAYER M5 ;
        RECT  29.664 53.916 29.688 54 ;
    END
  END rq_row[7]
  PIN rq_row[8]
    DIRECTION OUTPUT ;
    USE SIGNAL ;
    PORT
      LAYER M5 ;
        RECT  29.76 53.916 29.784 54 ;
    END
  END rq_row[8]
  PIN rq_row[9]
    DIRECTION OUTPUT ;
    USE SIGNAL ;
    PORT
      LAYER M5 ;
        RECT  29.856 53.916 29.88 54 ;
    END
  END rq_row[9]
  PIN rq_v[0]
    DIRECTION OUTPUT ;
    USE SIGNAL ;
    PORT
      LAYER M5 ;
        RECT  27.552 53.916 27.576 54 ;
    END
  END rq_v[0]
  PIN rq_v[1]
    DIRECTION OUTPUT ;
    USE SIGNAL ;
    PORT
      LAYER M5 ;
        RECT  27.648 53.916 27.672 54 ;
    END
  END rq_v[1]
  PIN rq_v[2]
    DIRECTION OUTPUT ;
    USE SIGNAL ;
    PORT
      LAYER M5 ;
        RECT  27.744 53.916 27.768 54 ;
    END
  END rq_v[2]
  PIN rq_v[3]
    DIRECTION OUTPUT ;
    USE SIGNAL ;
    PORT
      LAYER M5 ;
        RECT  27.84 53.916 27.864 54 ;
    END
  END rq_v[3]
  PIN rq_v[4]
    DIRECTION OUTPUT ;
    USE SIGNAL ;
    PORT
      LAYER M5 ;
        RECT  27.936 53.916 27.96 54 ;
    END
  END rq_v[4]
  PIN rs_v[0]
    DIRECTION INPUT ;
    USE SIGNAL ;
    PORT
      LAYER M5 ;
        RECT  37.728 53.916 37.752 54 ;
    END
  END rs_v[0]
  PIN rs_v[1]
    DIRECTION INPUT ;
    USE SIGNAL ;
    PORT
      LAYER M5 ;
        RECT  37.824 53.916 37.848 54 ;
    END
  END rs_v[1]
  PIN rs_v[2]
    DIRECTION INPUT ;
    USE SIGNAL ;
    PORT
      LAYER M5 ;
        RECT  37.92 53.916 37.944 54 ;
    END
  END rs_v[2]
  PIN rs_v[3]
    DIRECTION INPUT ;
    USE SIGNAL ;
    PORT
      LAYER M5 ;
        RECT  38.016 53.916 38.04 54 ;
    END
  END rs_v[3]
  PIN rs_v[4]
    DIRECTION INPUT ;
    USE SIGNAL ;
    PORT
      LAYER M5 ;
        RECT  38.112 53.916 38.136 54 ;
    END
  END rs_v[4]
  PIN rst
    DIRECTION INPUT ;
    USE SIGNAL ;
    PORT
      LAYER M4 ;
        RECT  0 4.992 0.084 5.016 ;
    END
  END rst
  PIN scale[0]
    DIRECTION OUTPUT ;
    USE SIGNAL ;
    PORT
      LAYER M5 ;
        RECT  14.496 0 14.52 0.084 ;
    END
  END scale[0]
  PIN scale[10]
    DIRECTION OUTPUT ;
    USE SIGNAL ;
    PORT
      LAYER M5 ;
        RECT  15.456 0 15.48 0.084 ;
    END
  END scale[10]
  PIN scale[11]
    DIRECTION OUTPUT ;
    USE SIGNAL ;
    PORT
      LAYER M5 ;
        RECT  15.552 0 15.576 0.084 ;
    END
  END scale[11]
  PIN scale[12]
    DIRECTION OUTPUT ;
    USE SIGNAL ;
    PORT
      LAYER M5 ;
        RECT  15.648 0 15.672 0.084 ;
    END
  END scale[12]
  PIN scale[13]
    DIRECTION OUTPUT ;
    USE SIGNAL ;
    PORT
      LAYER M5 ;
        RECT  15.744 0 15.768 0.084 ;
    END
  END scale[13]
  PIN scale[14]
    DIRECTION OUTPUT ;
    USE SIGNAL ;
    PORT
      LAYER M5 ;
        RECT  15.84 0 15.864 0.084 ;
    END
  END scale[14]
  PIN scale[15]
    DIRECTION OUTPUT ;
    USE SIGNAL ;
    PORT
      LAYER M5 ;
        RECT  15.936 0 15.96 0.084 ;
    END
  END scale[15]
  PIN scale[16]
    DIRECTION OUTPUT ;
    USE SIGNAL ;
    PORT
      LAYER M5 ;
        RECT  16.032 0 16.056 0.084 ;
    END
  END scale[16]
  PIN scale[17]
    DIRECTION OUTPUT ;
    USE SIGNAL ;
    PORT
      LAYER M5 ;
        RECT  16.128 0 16.152 0.084 ;
    END
  END scale[17]
  PIN scale[18]
    DIRECTION OUTPUT ;
    USE SIGNAL ;
    PORT
      LAYER M5 ;
        RECT  16.224 0 16.248 0.084 ;
    END
  END scale[18]
  PIN scale[19]
    DIRECTION OUTPUT ;
    USE SIGNAL ;
    PORT
      LAYER M5 ;
        RECT  16.32 0 16.344 0.084 ;
    END
  END scale[19]
  PIN scale[1]
    DIRECTION OUTPUT ;
    USE SIGNAL ;
    PORT
      LAYER M5 ;
        RECT  14.592 0 14.616 0.084 ;
    END
  END scale[1]
  PIN scale[20]
    DIRECTION OUTPUT ;
    USE SIGNAL ;
    PORT
      LAYER M5 ;
        RECT  16.416 0 16.44 0.084 ;
    END
  END scale[20]
  PIN scale[21]
    DIRECTION OUTPUT ;
    USE SIGNAL ;
    PORT
      LAYER M5 ;
        RECT  16.512 0 16.536 0.084 ;
    END
  END scale[21]
  PIN scale[22]
    DIRECTION OUTPUT ;
    USE SIGNAL ;
    PORT
      LAYER M5 ;
        RECT  16.608 0 16.632 0.084 ;
    END
  END scale[22]
  PIN scale[23]
    DIRECTION OUTPUT ;
    USE SIGNAL ;
    PORT
      LAYER M5 ;
        RECT  16.704 0 16.728 0.084 ;
    END
  END scale[23]
  PIN scale[24]
    DIRECTION OUTPUT ;
    USE SIGNAL ;
    PORT
      LAYER M5 ;
        RECT  16.8 0 16.824 0.084 ;
    END
  END scale[24]
  PIN scale[25]
    DIRECTION OUTPUT ;
    USE SIGNAL ;
    PORT
      LAYER M5 ;
        RECT  16.896 0 16.92 0.084 ;
    END
  END scale[25]
  PIN scale[26]
    DIRECTION OUTPUT ;
    USE SIGNAL ;
    PORT
      LAYER M5 ;
        RECT  16.992 0 17.016 0.084 ;
    END
  END scale[26]
  PIN scale[27]
    DIRECTION OUTPUT ;
    USE SIGNAL ;
    PORT
      LAYER M5 ;
        RECT  17.088 0 17.112 0.084 ;
    END
  END scale[27]
  PIN scale[28]
    DIRECTION OUTPUT ;
    USE SIGNAL ;
    PORT
      LAYER M5 ;
        RECT  17.184 0 17.208 0.084 ;
    END
  END scale[28]
  PIN scale[29]
    DIRECTION OUTPUT ;
    USE SIGNAL ;
    PORT
      LAYER M5 ;
        RECT  17.28 0 17.304 0.084 ;
    END
  END scale[29]
  PIN scale[2]
    DIRECTION OUTPUT ;
    USE SIGNAL ;
    PORT
      LAYER M5 ;
        RECT  14.688 0 14.712 0.084 ;
    END
  END scale[2]
  PIN scale[30]
    DIRECTION OUTPUT ;
    USE SIGNAL ;
    PORT
      LAYER M5 ;
        RECT  17.376 0 17.4 0.084 ;
    END
  END scale[30]
  PIN scale[31]
    DIRECTION OUTPUT ;
    USE SIGNAL ;
    PORT
      LAYER M5 ;
        RECT  17.472 0 17.496 0.084 ;
    END
  END scale[31]
  PIN scale[3]
    DIRECTION OUTPUT ;
    USE SIGNAL ;
    PORT
      LAYER M5 ;
        RECT  14.784 0 14.808 0.084 ;
    END
  END scale[3]
  PIN scale[4]
    DIRECTION OUTPUT ;
    USE SIGNAL ;
    PORT
      LAYER M5 ;
        RECT  14.88 0 14.904 0.084 ;
    END
  END scale[4]
  PIN scale[5]
    DIRECTION OUTPUT ;
    USE SIGNAL ;
    PORT
      LAYER M5 ;
        RECT  14.976 0 15 0.084 ;
    END
  END scale[5]
  PIN scale[6]
    DIRECTION OUTPUT ;
    USE SIGNAL ;
    PORT
      LAYER M5 ;
        RECT  15.072 0 15.096 0.084 ;
    END
  END scale[6]
  PIN scale[7]
    DIRECTION OUTPUT ;
    USE SIGNAL ;
    PORT
      LAYER M5 ;
        RECT  15.168 0 15.192 0.084 ;
    END
  END scale[7]
  PIN scale[8]
    DIRECTION OUTPUT ;
    USE SIGNAL ;
    PORT
      LAYER M5 ;
        RECT  15.264 0 15.288 0.084 ;
    END
  END scale[8]
  PIN scale[9]
    DIRECTION OUTPUT ;
    USE SIGNAL ;
    PORT
      LAYER M5 ;
        RECT  15.36 0 15.384 0.084 ;
    END
  END scale[9]
  PIN start
    DIRECTION INPUT ;
    USE SIGNAL ;
    PORT
      LAYER M5 ;
        RECT  4.032 53.916 4.056 54 ;
    END
    PORT
      LAYER M5 ;
        RECT  4.032 47.891 4.056 53.968 ;
    END
  END start
  PIN vtag
    DIRECTION OUTPUT ;
    USE SIGNAL ;
    PORT
      LAYER M5 ;
        RECT  36.672 53.916 36.696 54 ;
    END
    PORT
      LAYER M5 ;
        RECT  36.672 53.891 36.696 53.968 ;
    END
  END vtag
  PIN wq_mask[0]
    DIRECTION OUTPUT ;
    USE SIGNAL ;
    PORT
      LAYER M5 ;
        RECT  42.528 53.916 42.552 54 ;
    END
  END wq_mask[0]
  PIN wq_mask[10]
    DIRECTION OUTPUT ;
    USE SIGNAL ;
    PORT
      LAYER M5 ;
        RECT  43.488 53.916 43.512 54 ;
    END
  END wq_mask[10]
  PIN wq_mask[11]
    DIRECTION OUTPUT ;
    USE SIGNAL ;
    PORT
      LAYER M5 ;
        RECT  43.584 53.916 43.608 54 ;
    END
  END wq_mask[11]
  PIN wq_mask[12]
    DIRECTION OUTPUT ;
    USE SIGNAL ;
    PORT
      LAYER M5 ;
        RECT  43.68 53.916 43.704 54 ;
    END
  END wq_mask[12]
  PIN wq_mask[13]
    DIRECTION OUTPUT ;
    USE SIGNAL ;
    PORT
      LAYER M5 ;
        RECT  43.776 53.916 43.8 54 ;
    END
  END wq_mask[13]
  PIN wq_mask[14]
    DIRECTION OUTPUT ;
    USE SIGNAL ;
    PORT
      LAYER M5 ;
        RECT  43.872 53.916 43.896 54 ;
    END
  END wq_mask[14]
  PIN wq_mask[15]
    DIRECTION OUTPUT ;
    USE SIGNAL ;
    PORT
      LAYER M5 ;
        RECT  43.968 53.916 43.992 54 ;
    END
  END wq_mask[15]
  PIN wq_mask[1]
    DIRECTION OUTPUT ;
    USE SIGNAL ;
    PORT
      LAYER M5 ;
        RECT  42.624 53.916 42.648 54 ;
    END
  END wq_mask[1]
  PIN wq_mask[2]
    DIRECTION OUTPUT ;
    USE SIGNAL ;
    PORT
      LAYER M5 ;
        RECT  42.72 53.916 42.744 54 ;
    END
  END wq_mask[2]
  PIN wq_mask[3]
    DIRECTION OUTPUT ;
    USE SIGNAL ;
    PORT
      LAYER M5 ;
        RECT  42.816 53.916 42.84 54 ;
    END
  END wq_mask[3]
  PIN wq_mask[4]
    DIRECTION OUTPUT ;
    USE SIGNAL ;
    PORT
      LAYER M5 ;
        RECT  42.912 53.916 42.936 54 ;
    END
  END wq_mask[4]
  PIN wq_mask[5]
    DIRECTION OUTPUT ;
    USE SIGNAL ;
    PORT
      LAYER M5 ;
        RECT  43.008 53.916 43.032 54 ;
    END
  END wq_mask[5]
  PIN wq_mask[6]
    DIRECTION OUTPUT ;
    USE SIGNAL ;
    PORT
      LAYER M5 ;
        RECT  43.104 53.916 43.128 54 ;
    END
  END wq_mask[6]
  PIN wq_mask[7]
    DIRECTION OUTPUT ;
    USE SIGNAL ;
    PORT
      LAYER M5 ;
        RECT  43.2 53.916 43.224 54 ;
    END
  END wq_mask[7]
  PIN wq_mask[8]
    DIRECTION OUTPUT ;
    USE SIGNAL ;
    PORT
      LAYER M5 ;
        RECT  43.296 53.916 43.32 54 ;
    END
  END wq_mask[8]
  PIN wq_mask[9]
    DIRECTION OUTPUT ;
    USE SIGNAL ;
    PORT
      LAYER M5 ;
        RECT  43.392 53.916 43.416 54 ;
    END
  END wq_mask[9]
  PIN wq_row[0]
    DIRECTION OUTPUT ;
    USE SIGNAL ;
    PORT
      LAYER M5 ;
        RECT  40.224 53.916 40.248 54 ;
    END
  END wq_row[0]
  PIN wq_row[10]
    DIRECTION OUTPUT ;
    USE SIGNAL ;
    PORT
      LAYER M5 ;
        RECT  41.184 53.916 41.208 54 ;
    END
  END wq_row[10]
  PIN wq_row[11]
    DIRECTION OUTPUT ;
    USE SIGNAL ;
    PORT
      LAYER M5 ;
        RECT  41.28 53.916 41.304 54 ;
    END
  END wq_row[11]
  PIN wq_row[12]
    DIRECTION OUTPUT ;
    USE SIGNAL ;
    PORT
      LAYER M5 ;
        RECT  41.376 53.916 41.4 54 ;
    END
  END wq_row[12]
  PIN wq_row[13]
    DIRECTION OUTPUT ;
    USE SIGNAL ;
    PORT
      LAYER M5 ;
        RECT  41.472 53.916 41.496 54 ;
    END
  END wq_row[13]
  PIN wq_row[1]
    DIRECTION OUTPUT ;
    USE SIGNAL ;
    PORT
      LAYER M5 ;
        RECT  40.32 53.916 40.344 54 ;
    END
  END wq_row[1]
  PIN wq_row[2]
    DIRECTION OUTPUT ;
    USE SIGNAL ;
    PORT
      LAYER M5 ;
        RECT  40.416 53.916 40.44 54 ;
    END
  END wq_row[2]
  PIN wq_row[3]
    DIRECTION OUTPUT ;
    USE SIGNAL ;
    PORT
      LAYER M5 ;
        RECT  40.512 53.916 40.536 54 ;
    END
  END wq_row[3]
  PIN wq_row[4]
    DIRECTION OUTPUT ;
    USE SIGNAL ;
    PORT
      LAYER M5 ;
        RECT  40.608 53.916 40.632 54 ;
    END
  END wq_row[4]
  PIN wq_row[5]
    DIRECTION OUTPUT ;
    USE SIGNAL ;
    PORT
      LAYER M5 ;
        RECT  40.704 53.916 40.728 54 ;
    END
  END wq_row[5]
  PIN wq_row[6]
    DIRECTION OUTPUT ;
    USE SIGNAL ;
    PORT
      LAYER M5 ;
        RECT  40.8 53.916 40.824 54 ;
    END
  END wq_row[6]
  PIN wq_row[7]
    DIRECTION OUTPUT ;
    USE SIGNAL ;
    PORT
      LAYER M5 ;
        RECT  40.896 53.916 40.92 54 ;
    END
  END wq_row[7]
  PIN wq_row[8]
    DIRECTION OUTPUT ;
    USE SIGNAL ;
    PORT
      LAYER M5 ;
        RECT  40.992 53.916 41.016 54 ;
    END
  END wq_row[8]
  PIN wq_row[9]
    DIRECTION OUTPUT ;
    USE SIGNAL ;
    PORT
      LAYER M5 ;
        RECT  41.088 53.916 41.112 54 ;
    END
  END wq_row[9]
  PIN wq_v
    DIRECTION OUTPUT ;
    USE SIGNAL ;
    PORT
      LAYER M5 ;
        RECT  39.168 53.916 39.192 54 ;
    END
    PORT
      LAYER M5 ;
        RECT  39.168 53.891 39.192 53.968 ;
    END
  END wq_v
  PIN VDD
    DIRECTION INOUT ;
    USE POWER ;
    PORT
      LAYER M5 ;
        RECT  83.592 2.151 83.712 51.849 ;
        RECT  78.192 2.151 78.312 51.849 ;
        RECT  72.792 2.151 72.912 51.849 ;
        RECT  67.392 2.151 67.512 51.849 ;
        RECT  61.992 2.151 62.112 51.849 ;
        RECT  56.592 2.151 56.712 51.849 ;
        RECT  51.192 2.151 51.312 51.849 ;
        RECT  45.792 2.151 45.912 51.849 ;
        RECT  40.392 2.151 40.512 51.849 ;
        RECT  34.992 2.151 35.112 51.849 ;
        RECT  29.592 2.151 29.712 51.849 ;
        RECT  24.192 2.151 24.312 51.849 ;
        RECT  18.792 2.151 18.912 51.849 ;
        RECT  13.392 2.151 13.512 51.849 ;
        RECT  7.992 2.151 8.112 51.849 ;
        RECT  2.592 2.151 2.712 51.849 ;
    END
  END VDD
  PIN VSS
    DIRECTION INOUT ;
    USE GROUND ;
    PORT
      LAYER M5 ;
        RECT  83.4 2.137 83.52 51.863 ;
        RECT  78 2.137 78.12 51.863 ;
        RECT  72.6 2.137 72.72 51.863 ;
        RECT  67.2 2.137 67.32 51.863 ;
        RECT  61.8 2.137 61.92 51.863 ;
        RECT  56.4 2.137 56.52 51.863 ;
        RECT  51 2.137 51.12 51.863 ;
        RECT  45.6 2.137 45.72 51.863 ;
        RECT  40.2 2.137 40.32 51.863 ;
        RECT  34.8 2.137 34.92 51.863 ;
        RECT  29.4 2.137 29.52 51.863 ;
        RECT  24 2.137 24.12 51.863 ;
        RECT  18.6 2.137 18.72 51.863 ;
        RECT  13.2 2.137 13.32 51.863 ;
        RECT  7.8 2.137 7.92 51.863 ;
        RECT  2.4 2.137 2.52 51.863 ;
    END
  END VSS
  # OT_OBS_CLOSED layer=M5 d_um=1.536 added=97
  OBS
    LAYER RVTN ;
     RECT  2.16 2.16 84.24 2.295 ;
     RECT  2.16 2.565 84.24 2.835 ;
     RECT  2.16 3.105 84.24 3.375 ;
     RECT  2.16 3.645 84.24 3.915 ;
     RECT  2.16 4.185 84.24 4.455 ;
     RECT  2.16 4.725 84.24 4.995 ;
     RECT  2.16 5.265 84.24 5.535 ;
     RECT  2.16 5.805 84.24 6.075 ;
     RECT  2.16 6.345 84.24 6.615 ;
     RECT  2.16 6.885 84.24 7.155 ;
     RECT  2.16 7.425 84.24 7.695 ;
     RECT  2.16 7.965 84.24 8.235 ;
     RECT  2.16 8.505 84.24 8.775 ;
     RECT  2.16 9.045 84.24 9.315 ;
     RECT  2.16 9.585 84.24 9.855 ;
     RECT  2.16 10.125 84.24 10.395 ;
     RECT  2.16 10.665 84.24 10.935 ;
     RECT  2.16 11.205 84.24 11.475 ;
     RECT  2.16 11.745 84.24 12.015 ;
     RECT  2.16 12.285 84.24 12.555 ;
     RECT  2.16 12.825 84.24 13.095 ;
     RECT  2.16 13.365 84.24 13.635 ;
     RECT  2.16 13.905 84.24 14.175 ;
     RECT  2.16 14.445 84.24 14.715 ;
     RECT  2.16 14.985 84.24 15.255 ;
     RECT  2.16 15.525 84.24 15.795 ;
     RECT  2.16 16.065 84.24 16.335 ;
     RECT  2.16 16.605 84.24 16.875 ;
     RECT  2.16 17.145 84.24 17.415 ;
     RECT  2.16 17.685 84.24 17.955 ;
     RECT  2.16 18.225 84.24 18.495 ;
     RECT  2.16 18.765 84.24 19.035 ;
     RECT  2.16 19.305 84.24 19.575 ;
     RECT  2.16 19.845 84.24 20.115 ;
     RECT  2.16 20.385 84.24 20.655 ;
     RECT  2.16 20.925 84.24 21.195 ;
     RECT  2.16 21.465 84.24 21.735 ;
     RECT  2.16 22.005 84.24 22.275 ;
     RECT  2.16 22.545 84.24 22.815 ;
     RECT  2.16 23.085 84.24 23.355 ;
     RECT  2.16 23.625 84.24 23.895 ;
     RECT  2.16 24.165 84.24 24.435 ;
     RECT  2.16 24.705 84.24 24.975 ;
     RECT  2.16 25.245 84.24 25.515 ;
     RECT  2.16 25.785 84.24 26.055 ;
     RECT  2.16 26.325 84.24 26.595 ;
     RECT  2.16 26.865 84.24 27.135 ;
     RECT  2.16 27.405 84.24 27.675 ;
     RECT  2.16 27.945 84.24 28.215 ;
     RECT  2.16 28.485 84.24 28.755 ;
     RECT  2.16 29.025 84.24 29.295 ;
     RECT  2.16 29.565 84.24 29.835 ;
     RECT  2.16 30.105 84.24 30.375 ;
     RECT  2.16 30.645 84.24 30.915 ;
     RECT  2.16 31.185 84.24 31.455 ;
     RECT  2.16 31.725 84.24 31.995 ;
     RECT  2.16 32.265 84.24 32.535 ;
     RECT  2.16 32.805 84.24 33.075 ;
     RECT  2.16 33.345 84.24 33.615 ;
     RECT  2.16 33.885 84.24 34.155 ;
     RECT  2.16 34.425 84.24 34.695 ;
     RECT  2.16 34.965 84.24 35.235 ;
     RECT  2.16 35.505 84.24 35.775 ;
     RECT  2.16 36.045 84.24 36.315 ;
     RECT  2.16 36.585 84.24 36.855 ;
     RECT  2.16 37.125 84.24 37.395 ;
     RECT  2.16 37.665 84.24 37.935 ;
     RECT  2.16 38.205 84.24 38.475 ;
     RECT  2.16 38.745 84.24 39.015 ;
     RECT  2.16 39.285 84.24 39.555 ;
     RECT  2.16 39.825 84.24 40.095 ;
     RECT  2.16 40.365 84.24 40.635 ;
     RECT  2.16 40.905 84.24 41.175 ;
     RECT  2.16 41.445 84.24 41.715 ;
     RECT  2.16 41.985 84.24 42.255 ;
     RECT  2.16 42.525 84.24 42.795 ;
     RECT  2.16 43.065 84.24 43.335 ;
     RECT  2.16 43.605 84.24 43.875 ;
     RECT  2.16 44.145 84.24 44.415 ;
     RECT  2.16 44.685 84.24 44.955 ;
     RECT  2.16 45.225 84.24 45.495 ;
     RECT  2.16 45.765 84.24 46.035 ;
     RECT  2.16 46.305 84.24 46.575 ;
     RECT  2.16 46.845 84.24 47.115 ;
     RECT  2.16 47.385 84.24 47.655 ;
     RECT  2.16 47.925 84.24 48.195 ;
     RECT  2.16 48.465 84.24 48.735 ;
     RECT  2.16 49.005 84.24 49.275 ;
     RECT  2.16 49.545 84.24 49.815 ;
     RECT  2.16 50.085 84.24 50.355 ;
     RECT  2.16 50.625 84.24 50.895 ;
     RECT  2.16 51.165 84.24 51.435 ;
     RECT  2.16 51.705 84.24 51.84 ;
    LAYER RVTP ;
     RECT  2.16 2.295 84.24 2.565 ;
     RECT  2.16 2.835 84.24 3.105 ;
     RECT  2.16 3.375 84.24 3.645 ;
     RECT  2.16 3.915 84.24 4.185 ;
     RECT  2.16 4.455 84.24 4.725 ;
     RECT  2.16 4.995 84.24 5.265 ;
     RECT  2.16 5.535 84.24 5.805 ;
     RECT  2.16 6.075 84.24 6.345 ;
     RECT  2.16 6.615 84.24 6.885 ;
     RECT  2.16 7.155 84.24 7.425 ;
     RECT  2.16 7.695 84.24 7.965 ;
     RECT  2.16 8.235 84.24 8.505 ;
     RECT  2.16 8.775 84.24 9.045 ;
     RECT  2.16 9.315 84.24 9.585 ;
     RECT  2.16 9.855 84.24 10.125 ;
     RECT  2.16 10.395 84.24 10.665 ;
     RECT  2.16 10.935 84.24 11.205 ;
     RECT  2.16 11.475 84.24 11.745 ;
     RECT  2.16 12.015 84.24 12.285 ;
     RECT  2.16 12.555 84.24 12.825 ;
     RECT  2.16 13.095 84.24 13.365 ;
     RECT  2.16 13.635 84.24 13.905 ;
     RECT  2.16 14.175 84.24 14.445 ;
     RECT  2.16 14.715 84.24 14.985 ;
     RECT  2.16 15.255 84.24 15.525 ;
     RECT  2.16 15.795 84.24 16.065 ;
     RECT  2.16 16.335 84.24 16.605 ;
     RECT  2.16 16.875 84.24 17.145 ;
     RECT  2.16 17.415 84.24 17.685 ;
     RECT  2.16 17.955 84.24 18.225 ;
     RECT  2.16 18.495 84.24 18.765 ;
     RECT  2.16 19.035 84.24 19.305 ;
     RECT  2.16 19.575 84.24 19.845 ;
     RECT  2.16 20.115 84.24 20.385 ;
     RECT  2.16 20.655 84.24 20.925 ;
     RECT  2.16 21.195 84.24 21.465 ;
     RECT  2.16 21.735 84.24 22.005 ;
     RECT  2.16 22.275 84.24 22.545 ;
     RECT  2.16 22.815 84.24 23.085 ;
     RECT  2.16 23.355 84.24 23.625 ;
     RECT  2.16 23.895 84.24 24.165 ;
     RECT  2.16 24.435 84.24 24.705 ;
     RECT  2.16 24.975 84.24 25.245 ;
     RECT  2.16 25.515 84.24 25.785 ;
     RECT  2.16 26.055 84.24 26.325 ;
     RECT  2.16 26.595 84.24 26.865 ;
     RECT  2.16 27.135 84.24 27.405 ;
     RECT  2.16 27.675 84.24 27.945 ;
     RECT  2.16 28.215 84.24 28.485 ;
     RECT  2.16 28.755 84.24 29.025 ;
     RECT  2.16 29.295 84.24 29.565 ;
     RECT  2.16 29.835 84.24 30.105 ;
     RECT  2.16 30.375 84.24 30.645 ;
     RECT  2.16 30.915 84.24 31.185 ;
     RECT  2.16 31.455 84.24 31.725 ;
     RECT  2.16 31.995 84.24 32.265 ;
     RECT  2.16 32.535 84.24 32.805 ;
     RECT  2.16 33.075 84.24 33.345 ;
     RECT  2.16 33.615 84.24 33.885 ;
     RECT  2.16 34.155 84.24 34.425 ;
     RECT  2.16 34.695 84.24 34.965 ;
     RECT  2.16 35.235 84.24 35.505 ;
     RECT  2.16 35.775 84.24 36.045 ;
     RECT  2.16 36.315 84.24 36.585 ;
     RECT  2.16 36.855 84.24 37.125 ;
     RECT  2.16 37.395 84.24 37.665 ;
     RECT  2.16 37.935 84.24 38.205 ;
     RECT  2.16 38.475 84.24 38.745 ;
     RECT  2.16 39.015 84.24 39.285 ;
     RECT  2.16 39.555 84.24 39.825 ;
     RECT  2.16 40.095 84.24 40.365 ;
     RECT  2.16 40.635 84.24 40.905 ;
     RECT  2.16 41.175 84.24 41.445 ;
     RECT  2.16 41.715 84.24 41.985 ;
     RECT  2.16 42.255 84.24 42.525 ;
     RECT  2.16 42.795 84.24 43.065 ;
     RECT  2.16 43.335 84.24 43.605 ;
     RECT  2.16 43.875 84.24 44.145 ;
     RECT  2.16 44.415 84.24 44.685 ;
     RECT  2.16 44.955 84.24 45.225 ;
     RECT  2.16 45.495 84.24 45.765 ;
     RECT  2.16 46.035 84.24 46.305 ;
     RECT  2.16 46.575 84.24 46.845 ;
     RECT  2.16 47.115 84.24 47.385 ;
     RECT  2.16 47.655 84.24 47.925 ;
     RECT  2.16 48.195 84.24 48.465 ;
     RECT  2.16 48.735 84.24 49.005 ;
     RECT  2.16 49.275 84.24 49.545 ;
     RECT  2.16 49.815 84.24 50.085 ;
     RECT  2.16 50.355 84.24 50.625 ;
     RECT  2.16 50.895 84.24 51.165 ;
     RECT  2.16 51.435 84.24 51.705 ;
    LAYER M1 ;
     RECT  2.16 2.151 84.24 51.849 ;
    LAYER M2 ;
     RECT  2.16 2.151 4.675 51.849 ;
     RECT  4.675 2.106 5.423 51.849 ;
     RECT  5.423 2.151 7.375 51.849 ;
     RECT  7.375 2.106 8.447 51.849 ;
     RECT  8.447 2.151 12.523 51.849 ;
     RECT  12.523 2.106 12.911 51.849 ;
     RECT  13.963 1.152 14.063 1.17 ;
     RECT  12.911 2.151 84.24 51.849 ;
    LAYER M3 ;
     RECT  11.952 0.091 11.97 0.571 ;
     RECT  12.96 0.091 12.978 0.571 ;
     RECT  19.584 0.091 19.602 0.571 ;
     RECT  10.476 0.523 11.214 1.099 ;
     RECT  11.952 0.571 12.978 1.099 ;
     RECT  10.476 1.099 12.978 1.147 ;
     RECT  13.968 0.139 13.986 1.147 ;
     RECT  16.776 1.147 16.794 1.579 ;
     RECT  10.476 1.147 14.67 1.723 ;
     RECT  16.776 1.579 17.046 1.723 ;
     RECT  19.44 0.571 19.602 1.723 ;
     RECT  21.78 0.571 21.798 1.723 ;
     RECT  15.876 1.723 17.046 1.771 ;
     RECT  17.964 1.723 18.558 1.771 ;
     RECT  15.876 1.771 18.558 1.819 ;
     RECT  15.66 1.819 18.558 1.867 ;
     RECT  4.248 0.091 4.266 2.101 ;
     RECT  5.04 0.091 5.058 2.101 ;
     RECT  7.2 0.091 7.218 2.101 ;
     RECT  8.208 0.091 8.226 2.101 ;
     RECT  9.108 0.091 9.45 2.101 ;
     RECT  7.2 2.101 7.398 2.143 ;
     RECT  8.208 2.101 9.45 2.143 ;
     RECT  15.66 1.867 18.594 2.143 ;
     RECT  7.2 2.143 9.45 2.191 ;
     RECT  10.476 1.723 14.814 2.191 ;
     RECT  15.66 2.143 18.705 2.191 ;
     RECT  22.824 0.571 22.842 2.255 ;
     RECT  4.248 2.101 5.418 2.263 ;
     RECT  6.156 1.723 6.174 2.263 ;
     RECT  10.476 2.191 18.705 2.263 ;
     RECT  4.248 2.263 6.174 2.335 ;
     RECT  7.2 2.191 9.522 2.335 ;
     RECT  4.248 2.335 9.522 2.371 ;
     RECT  10.44 2.263 18.705 2.371 ;
     RECT  19.44 1.723 19.638 2.371 ;
     RECT  20.772 1.723 20.79 2.371 ;
     RECT  21.78 1.723 21.87 2.371 ;
     RECT  2.415 2.143 2.505 2.413 ;
     RECT  24.015 2.143 24.105 2.413 ;
     RECT  29.415 2.143 29.505 2.413 ;
     RECT  34.815 2.143 34.905 2.413 ;
     RECT  40.215 2.143 40.305 2.413 ;
     RECT  45.615 2.143 45.705 2.413 ;
     RECT  51.015 2.143 51.105 2.413 ;
     RECT  56.415 2.143 56.505 2.413 ;
     RECT  61.815 2.143 61.905 2.413 ;
     RECT  67.215 2.143 67.305 2.413 ;
     RECT  72.615 2.143 72.705 2.413 ;
     RECT  78.015 2.143 78.105 2.413 ;
     RECT  83.415 2.143 83.505 2.413 ;
     RECT  4.14 2.371 9.522 2.489 ;
     RECT  4.14 2.489 6.534 2.525 ;
     RECT  10.404 2.371 20.79 2.525 ;
     RECT  7.815 2.489 9.522 2.569 ;
     RECT  10.404 2.525 20.142 2.569 ;
     RECT  21.708 2.371 22.302 2.641 ;
     RECT  4.968 2.525 6.534 2.669 ;
     RECT  7.815 2.569 20.142 2.831 ;
     RECT  9.504 2.831 20.142 3.641 ;
     RECT  9.576 3.641 20.142 4.153 ;
     RECT  21.456 2.641 22.302 4.153 ;
     RECT  4.968 2.669 5.49 4.261 ;
     RECT  2.415 2.413 2.697 4.657 ;
     RECT  9.576 4.153 22.302 4.657 ;
     RECT  2.415 4.657 3.33 4.693 ;
     RECT  4.968 4.261 5.526 4.765 ;
     RECT  24.015 2.413 24.297 4.765 ;
     RECT  2.415 4.693 3.546 4.801 ;
     RECT  7.815 2.831 8.658 4.801 ;
     RECT  9.504 4.657 22.302 4.801 ;
     RECT  23.148 2.371 23.166 4.801 ;
     RECT  24.015 4.765 24.606 4.801 ;
     RECT  2.415 4.801 3.87 4.927 ;
     RECT  23.148 4.801 24.75 4.927 ;
     RECT  7.815 4.801 22.302 4.999 ;
     RECT  2.304 4.927 3.87 5.029 ;
     RECT  6.516 2.669 6.534 5.035 ;
     RECT  7.56 4.999 22.302 5.035 ;
     RECT  23.076 4.927 24.75 5.035 ;
     RECT  2.304 5.029 4.158 5.071 ;
     RECT  4.932 4.765 5.526 5.071 ;
     RECT  6.516 5.035 24.93 5.071 ;
     RECT  2.304 5.071 5.526 5.131 ;
     RECT  6.444 5.071 24.93 5.131 ;
     RECT  2.304 5.131 24.93 5.161 ;
     RECT  2.304 5.161 25.29 5.467 ;
     RECT  26.028 5.341 26.046 5.467 ;
     RECT  2.304 5.467 26.046 5.495 ;
     RECT  2.415 5.495 26.046 5.639 ;
     RECT  2.415 5.639 5.346 5.645 ;
     RECT  6.192 5.639 26.046 5.645 ;
     RECT  3.492 5.645 5.346 5.729 ;
     RECT  3.492 5.729 3.51 5.765 ;
     RECT  6.264 5.645 26.046 5.881 ;
     RECT  4.284 5.729 5.346 5.999 ;
     RECT  4.284 5.999 4.59 6.035 ;
     RECT  6.264 5.881 26.298 6.269 ;
     RECT  6.804 6.269 26.298 6.341 ;
     RECT  7.164 6.341 26.298 9.661 ;
     RECT  6.948 9.661 26.298 9.689 ;
     RECT  8.82 9.689 26.298 11.399 ;
     RECT  16.848 11.399 26.298 11.669 ;
     RECT  8.82 11.399 16.11 11.741 ;
     RECT  8.82 11.741 15.966 11.939 ;
     RECT  8.82 11.939 15.03 12.029 ;
     RECT  15.948 11.939 15.966 12.317 ;
     RECT  12.204 12.029 15.03 12.479 ;
     RECT  12.204 12.479 14.958 12.623 ;
     RECT  12.204 12.623 14.922 13.019 ;
     RECT  8.82 12.029 11.25 22.027 ;
     RECT  12.204 13.019 12.222 22.027 ;
     RECT  8.82 22.027 12.222 22.073 ;
     RECT  12.204 22.073 12.222 22.171 ;
     RECT  13.215 13.019 14.922 22.171 ;
     RECT  12.204 22.171 14.922 22.208 ;
     RECT  18.072 11.669 26.298 30.811 ;
     RECT  18.072 30.811 26.406 30.839 ;
     RECT  19.62 30.839 25.614 31.963 ;
     RECT  26.388 30.839 26.406 31.963 ;
     RECT  5.328 5.999 5.346 32.225 ;
     RECT  18.072 30.839 18.897 32.639 ;
     RECT  19.62 31.963 26.406 32.737 ;
     RECT  27.144 7.231 27.162 32.737 ;
     RECT  19.62 32.737 27.162 32.773 ;
     RECT  6.948 9.689 8.097 32.801 ;
     RECT  19.62 32.773 27.27 32.881 ;
     RECT  29.415 2.413 29.697 33.079 ;
     RECT  19.62 32.881 27.378 33.241 ;
     RECT  19.62 33.241 27.882 33.349 ;
     RECT  19.62 33.349 27.954 33.385 ;
     RECT  28.692 33.079 29.697 33.385 ;
     RECT  18.615 32.639 18.897 33.421 ;
     RECT  18.504 33.421 18.897 33.619 ;
     RECT  19.62 33.385 29.697 33.619 ;
     RECT  18.504 33.619 29.697 33.643 ;
     RECT  18.324 33.643 29.697 33.889 ;
     RECT  4.284 6.035 4.302 33.917 ;
     RECT  16.848 11.669 16.866 33.961 ;
     RECT  8.82 22.073 11.25 34.223 ;
     RECT  17.676 33.889 29.697 34.349 ;
     RECT  8.928 34.223 11.25 34.493 ;
     RECT  8.964 34.493 11.25 34.529 ;
     RECT  6.948 32.801 6.966 34.771 ;
     RECT  13.215 22.208 14.922 34.771 ;
     RECT  6.948 34.771 7.038 34.799 ;
     RECT  13.215 34.771 15.066 34.889 ;
     RECT  16.848 33.961 16.938 34.891 ;
     RECT  17.676 34.349 28.026 34.891 ;
     RECT  16.848 34.891 28.026 35.437 ;
     RECT  16.812 35.437 28.242 35.473 ;
     RECT  29.415 34.349 29.697 35.473 ;
     RECT  16.812 35.473 29.697 35.707 ;
     RECT  16.812 35.707 29.898 35.815 ;
     RECT  34.815 2.413 35.097 35.815 ;
     RECT  16.812 35.815 30.114 35.851 ;
     RECT  34.815 35.815 35.55 35.851 ;
     RECT  34.815 35.851 35.766 35.977 ;
     RECT  34.272 35.977 35.802 36.013 ;
     RECT  36.576 35.977 36.594 36.013 ;
     RECT  16.812 35.851 30.258 36.049 ;
     RECT  9.324 34.529 11.25 36.121 ;
     RECT  34.272 36.013 36.594 36.121 ;
     RECT  9.252 36.121 11.25 36.211 ;
     RECT  34.272 36.121 37.062 36.355 ;
     RECT  32.184 36.355 32.202 36.391 ;
     RECT  16.272 36.049 30.258 36.427 ;
     RECT  9.252 36.211 11.322 36.509 ;
     RECT  15.84 36.427 30.258 36.517 ;
     RECT  32.004 36.391 32.202 36.517 ;
     RECT  15.84 36.517 30.834 36.523 ;
     RECT  31.608 36.517 32.202 36.523 ;
     RECT  7.02 34.799 7.038 36.625 ;
     RECT  7.815 32.801 8.097 36.625 ;
     RECT  33.156 36.553 33.174 36.625 ;
     RECT  34.236 36.355 37.062 36.625 ;
     RECT  15.84 36.523 32.202 36.661 ;
     RECT  34.236 36.625 37.098 36.661 ;
     RECT  33.12 36.625 33.174 36.751 ;
     RECT  15.804 36.661 32.202 36.787 ;
     RECT  34.128 36.661 37.098 36.811 ;
     RECT  13.215 34.889 14.994 36.859 ;
     RECT  15.804 36.787 32.382 36.859 ;
     RECT  33.12 36.751 33.282 36.859 ;
     RECT  34.128 36.811 37.602 36.859 ;
     RECT  13.215 36.859 32.382 36.895 ;
     RECT  33.12 36.859 37.602 36.895 ;
     RECT  13.215 36.895 37.602 36.923 ;
     RECT  17.604 36.923 37.602 36.931 ;
     RECT  5.508 36.661 5.526 37.049 ;
     RECT  17.604 36.931 37.818 37.049 ;
     RECT  40.215 2.413 40.497 37.129 ;
     RECT  39.492 37.129 40.497 37.201 ;
     RECT  5.328 37.165 5.346 37.229 ;
     RECT  12.204 22.208 12.222 37.471 ;
     RECT  39.096 37.201 40.497 37.471 ;
     RECT  12.204 37.471 12.294 37.741 ;
     RECT  13.215 36.923 16.866 37.741 ;
     RECT  12.204 37.741 16.866 37.867 ;
     RECT  17.604 37.049 37.602 37.867 ;
     RECT  7.02 36.625 8.097 37.939 ;
     RECT  12.204 37.867 37.602 38.107 ;
     RECT  9.576 36.509 11.322 38.137 ;
     RECT  12.204 38.107 37.746 38.137 ;
     RECT  9.576 38.137 37.746 38.173 ;
     RECT  9.216 38.173 37.746 38.245 ;
     RECT  9.144 38.245 37.746 38.443 ;
     RECT  9.036 38.443 37.746 38.515 ;
     RECT  38.916 37.471 40.497 38.515 ;
     RECT  6.84 37.939 8.097 38.551 ;
     RECT  9.036 38.515 37.998 38.551 ;
     RECT  38.736 38.515 40.734 38.551 ;
     RECT  9.036 38.551 40.734 38.669 ;
     RECT  6.804 38.551 8.097 38.785 ;
     RECT  9.036 38.669 40.497 38.785 ;
     RECT  41.616 37.975 41.634 38.939 ;
     RECT  42.732 37.099 42.75 38.939 ;
     RECT  45.615 2.413 45.897 39.055 ;
     RECT  6.804 38.785 40.497 39.091 ;
     RECT  6.156 39.091 40.497 39.181 ;
     RECT  5.544 39.181 40.497 39.253 ;
     RECT  41.436 39.055 41.454 39.341 ;
     RECT  5.22 39.253 40.497 39.595 ;
     RECT  3.708 39.055 3.726 39.757 ;
     RECT  3.528 39.757 3.726 39.793 ;
     RECT  5.22 39.595 40.914 39.821 ;
     RECT  3.528 39.793 3.762 39.865 ;
     RECT  3.528 39.865 3.834 39.991 ;
     RECT  3.42 39.991 3.834 40.135 ;
     RECT  5.544 39.821 40.914 40.163 ;
     RECT  6.084 40.163 40.914 40.171 ;
     RECT  42.192 39.019 42.246 40.171 ;
     RECT  6.084 40.171 42.75 40.595 ;
     RECT  3.42 40.135 4.482 41.107 ;
     RECT  3.42 41.107 4.554 41.215 ;
     RECT  6.552 40.595 42.75 41.251 ;
     RECT  6.552 41.251 42.858 41.485 ;
     RECT  6.552 41.485 43.146 41.521 ;
     RECT  6.552 41.521 43.542 41.639 ;
     RECT  6.552 41.639 43.326 41.683 ;
     RECT  3.42 41.215 4.842 41.989 ;
     RECT  2.415 5.645 2.697 42.043 ;
     RECT  3.42 41.989 4.878 42.043 ;
     RECT  2.415 42.043 4.878 42.061 ;
     RECT  6.228 41.683 43.326 42.061 ;
     RECT  6.012 42.061 43.326 42.259 ;
     RECT  2.415 42.061 5.058 42.421 ;
     RECT  5.868 42.259 43.326 42.421 ;
     RECT  2.415 42.421 43.326 42.457 ;
     RECT  2.415 42.457 43.47 42.601 ;
     RECT  44.568 36.661 44.586 42.601 ;
     RECT  2.415 42.601 44.586 43.105 ;
     RECT  45.615 39.055 46.422 43.105 ;
     RECT  2.415 43.105 46.422 44.221 ;
     RECT  2.415 44.221 46.962 44.491 ;
     RECT  2.415 44.491 47.286 44.753 ;
     RECT  2.415 44.753 47.142 44.915 ;
     RECT  2.415 44.915 46.962 45.221 ;
     RECT  2.415 45.221 6.03 46.039 ;
     RECT  2.415 46.039 6.138 46.111 ;
     RECT  6.876 45.221 46.962 46.111 ;
     RECT  2.415 46.111 46.962 46.309 ;
     RECT  2.415 46.309 47.106 46.643 ;
     RECT  2.415 46.643 2.697 46.651 ;
     RECT  3.456 46.643 47.106 47.687 ;
     RECT  2.376 46.651 2.697 47.695 ;
     RECT  3.456 47.687 47.034 47.695 ;
     RECT  2.376 47.695 47.034 47.849 ;
     RECT  2.376 47.849 46.962 48.263 ;
     RECT  2.415 48.263 46.962 48.389 ;
     RECT  3.42 48.389 46.962 49.001 ;
     RECT  2.415 48.389 2.697 49.315 ;
     RECT  3.42 49.001 46.098 49.315 ;
     RECT  2.415 49.315 46.098 49.919 ;
     RECT  27.324 49.919 46.098 50.729 ;
     RECT  2.415 49.919 26.478 50.935 ;
     RECT  27.324 50.729 46.026 50.935 ;
     RECT  2.415 50.935 46.026 50.963 ;
     RECT  2.415 50.963 2.754 51.089 ;
     RECT  3.996 50.963 46.026 51.269 ;
     RECT  4.248 51.269 46.026 51.359 ;
     RECT  39.996 51.359 46.026 51.475 ;
     RECT  46.944 49.001 46.962 51.475 ;
     RECT  39.996 51.475 46.962 51.511 ;
     RECT  4.248 51.359 39.222 51.539 ;
     RECT  2.415 51.089 2.697 51.587 ;
     RECT  4.248 51.539 38.466 51.587 ;
     RECT  51.015 2.413 51.297 51.587 ;
     RECT  56.415 2.413 56.697 51.587 ;
     RECT  61.815 2.413 62.097 51.587 ;
     RECT  67.215 2.413 67.497 51.587 ;
     RECT  72.615 2.413 72.897 51.587 ;
     RECT  78.015 2.413 78.297 51.587 ;
     RECT  83.415 2.413 83.697 51.587 ;
     RECT  14.112 51.587 38.466 51.629 ;
     RECT  39.996 51.511 46.998 51.629 ;
     RECT  16.812 51.629 33.642 51.677 ;
     RECT  14.112 51.629 16.002 51.701 ;
     RECT  16.812 51.677 19.098 51.701 ;
     RECT  19.944 51.677 33.642 51.701 ;
     RECT  34.488 51.629 38.178 51.701 ;
     RECT  42.444 51.629 46.602 51.701 ;
     RECT  4.248 51.587 13.305 51.737 ;
     RECT  14.112 51.701 15.642 51.737 ;
     RECT  17.28 51.701 19.098 51.737 ;
     RECT  4.788 51.737 13.305 51.773 ;
     RECT  17.424 51.737 18.774 51.773 ;
     RECT  19.944 51.701 33.21 51.773 ;
     RECT  7.668 51.773 13.305 51.809 ;
     RECT  19.98 51.773 33.21 51.809 ;
     RECT  34.488 51.701 36.486 51.809 ;
     RECT  39.996 51.629 41.526 51.809 ;
     RECT  42.624 51.701 46.602 51.809 ;
     RECT  4.788 51.773 6.822 51.821 ;
     RECT  14.112 51.737 15.57 51.821 ;
     RECT  34.488 51.809 35.154 51.821 ;
     RECT  37.512 51.701 38.178 51.821 ;
     RECT  2.415 51.587 2.505 51.857 ;
     RECT  10.8 51.809 13.305 51.857 ;
     RECT  34.815 51.821 35.154 51.857 ;
     RECT  40.215 51.809 41.526 51.857 ;
     RECT  45.144 51.809 46.134 51.857 ;
     RECT  51.015 51.587 51.105 51.857 ;
     RECT  56.415 51.587 56.505 51.857 ;
     RECT  61.815 51.587 61.905 51.857 ;
     RECT  67.215 51.587 67.305 51.857 ;
     RECT  72.615 51.587 72.705 51.857 ;
     RECT  78.015 51.587 78.105 51.857 ;
     RECT  83.415 51.587 83.505 51.857 ;
     RECT  4.788 51.821 6.57 51.869 ;
     RECT  10.8 51.857 12.51 51.869 ;
     RECT  14.112 51.821 14.634 51.869 ;
     RECT  15.552 51.821 15.57 51.869 ;
     RECT  17.496 51.773 18.774 51.869 ;
     RECT  19.98 51.809 32.058 51.869 ;
     RECT  37.512 51.821 37.962 51.869 ;
     RECT  39.204 51.539 39.222 51.869 ;
     RECT  46.116 51.857 46.134 51.869 ;
     RECT  14.112 51.869 14.202 51.917 ;
     RECT  19.98 51.869 29.934 51.917 ;
     RECT  30.744 51.869 32.058 51.917 ;
     RECT  33.192 51.809 33.21 51.917 ;
     RECT  7.668 51.809 9.99 51.965 ;
     RECT  18.576 51.869 18.774 51.965 ;
     RECT  36.18 51.809 36.486 51.965 ;
     RECT  7.668 51.965 7.722 52.013 ;
     RECT  18.576 51.965 18.594 52.013 ;
     RECT  35.136 51.857 35.154 52.013 ;
     RECT  40.356 51.857 41.526 52.445 ;
     RECT  19.98 51.917 19.998 52.493 ;
     RECT  20.772 51.917 29.934 52.493 ;
     RECT  36.468 51.965 36.486 52.493 ;
     RECT  40.356 52.445 41.382 52.493 ;
     RECT  24.696 52.493 24.75 52.541 ;
     RECT  8.568 51.965 9.99 52.733 ;
     RECT  9.972 52.733 9.99 52.781 ;
     RECT  10.8 51.869 11.646 52.829 ;
     RECT  25.524 52.493 29.934 52.973 ;
     RECT  25.524 52.973 27.99 53.021 ;
     RECT  35.316 52.795 35.334 53.021 ;
     RECT  40.572 52.493 41.382 53.021 ;
     RECT  45.144 51.857 45.162 53.021 ;
     RECT  4.788 51.869 5.706 53.069 ;
     RECT  7.704 52.013 7.722 53.069 ;
     RECT  8.568 52.733 9.054 53.069 ;
     RECT  10.944 52.829 11.646 53.069 ;
     RECT  20.772 52.493 23.814 53.069 ;
     RECT  25.524 53.021 27.09 53.069 ;
     RECT  29.124 52.973 29.934 53.069 ;
     RECT  30.744 51.917 31.698 53.069 ;
     RECT  42.624 51.809 44.37 53.069 ;
     RECT  4.788 53.069 5.058 53.117 ;
     RECT  21.096 53.069 23.814 53.645 ;
     RECT  31.428 53.069 31.698 53.755 ;
     RECT  25.848 53.069 27.09 53.837 ;
     RECT  18.36 53.803 18.378 53.851 ;
     RECT  4.788 53.117 4.806 53.885 ;
     RECT  8.568 53.069 8.586 53.885 ;
     RECT  10.944 53.069 10.962 53.885 ;
     RECT  14.184 51.917 14.202 53.885 ;
     RECT  21.096 53.645 23.13 53.885 ;
     RECT  24.732 52.541 24.75 53.885 ;
     RECT  26.172 53.837 27.09 53.885 ;
     RECT  27.972 53.021 27.99 53.885 ;
     RECT  29.772 53.069 29.79 53.885 ;
     RECT  31.428 53.755 32.202 53.885 ;
     RECT  37.512 51.869 37.53 53.885 ;
     RECT  43.164 53.069 44.37 53.885 ;
     RECT  18.252 53.851 18.378 53.933 ;
     RECT  21.096 53.885 21.438 53.933 ;
     RECT  18.252 53.933 18.27 53.981 ;
     RECT  21.42 53.933 21.438 53.981 ;
    LAYER M4 ;
     RECT  0.06 4.032 0.227 5.016 ;
     RECT  0.227 4.992 2.408 5.016 ;
     RECT  0.181 27.696 2.408 27.72 ;
     RECT  2.408 2.148 2.512 51.852 ;
     RECT  2.512 2.418 2.704 51.582 ;
     RECT  2.704 49.584 2.819 50.856 ;
     RECT  2.819 49.584 2.981 50.136 ;
     RECT  2.704 47.856 3.692 48.072 ;
     RECT  2.704 45.792 3.697 45.816 ;
     RECT  3.697 45.648 3.737 45.816 ;
     RECT  3.692 47.232 3.779 48.072 ;
     RECT  2.981 49.584 3.805 50.04 ;
     RECT  3.779 47.808 3.949 48.072 ;
     RECT  2.704 41.136 4.025 42.6 ;
     RECT  2.704 5.184 4.129 5.64 ;
     RECT  3.737 45.648 4.165 45.672 ;
     RECT  3.841 43.776 4.201 43.8 ;
     RECT  4.165 45.024 4.201 45.672 ;
     RECT  3.949 47.808 4.241 48.12 ;
     RECT  4.129 5.04 4.259 5.64 ;
     RECT  4.201 43.776 4.261 45.672 ;
     RECT  3.805 49.392 4.345 50.04 ;
     RECT  4.025 41.136 4.565 42.216 ;
     RECT  4.345 49.392 4.705 50.616 ;
     RECT  4.705 49.392 4.817 51.336 ;
     RECT  4.241 47.856 4.885 48.12 ;
     RECT  4.817 49.392 4.885 50.04 ;
     RECT  4.565 42 4.889 42.216 ;
     RECT  4.813 52.464 4.993 52.488 ;
     RECT  4.777 53.856 4.993 53.88 ;
     RECT  4.021 0.096 5.123 0.12 ;
     RECT  4.993 52.464 5.219 53.88 ;
     RECT  5.219 52.992 5.315 53.88 ;
     RECT  4.021 37.2 5.357 37.224 ;
     RECT  5.209 39.792 5.365 39.816 ;
     RECT  5.365 39.792 5.411 40.344 ;
     RECT  4.261 43.296 5.411 45.672 ;
     RECT  4.817 51.312 5.425 51.336 ;
     RECT  5.315 52.992 5.507 53.112 ;
     RECT  5.125 46.752 5.645 46.776 ;
     RECT  4.885 47.856 5.653 50.04 ;
     RECT  5.507 53.04 5.699 53.112 ;
     RECT  5.653 46.896 5.709 50.04 ;
     RECT  5.699 53.04 5.987 53.064 ;
     RECT  5.709 48.672 6.041 50.04 ;
     RECT  5.425 51.312 6.109 51.864 ;
     RECT  6.101 1.728 6.185 1.752 ;
     RECT  6.181 5.616 6.217 5.64 ;
     RECT  4.889 42.048 6.217 42.216 ;
     RECT  5.411 43.296 6.217 45.048 ;
     RECT  6.217 42.048 6.361 45.048 ;
     RECT  6.109 51.12 6.401 51.864 ;
     RECT  5.411 40.32 6.577 40.344 ;
     RECT  6.401 51.312 6.581 51.864 ;
     RECT  6.361 42 6.709 45.048 ;
     RECT  5.709 46.896 6.709 47.4 ;
     RECT  6.709 42 6.721 47.4 ;
     RECT  6.721 41.664 6.761 47.4 ;
     RECT  6.577 39.84 6.793 40.344 ;
     RECT  6.793 39.792 6.829 40.344 ;
     RECT  6.217 5.136 7.297 5.64 ;
     RECT  6.761 47.136 7.369 47.4 ;
     RECT  6.041 48.672 7.369 49.464 ;
     RECT  6.581 51.312 7.657 51.816 ;
     RECT  7.297 5.136 7.729 6.36 ;
     RECT  7.729 5.04 7.808 6.36 ;
     RECT  4.213 22.176 7.808 22.2 ;
     RECT  2.704 27.696 7.808 27.72 ;
     RECT  7.153 38.64 7.808 38.664 ;
     RECT  6.829 39.792 7.808 40.68 ;
     RECT  6.761 41.664 7.808 46.104 ;
     RECT  7.369 47.136 7.808 49.464 ;
     RECT  7.657 51.312 7.808 52.008 ;
     RECT  7.808 2.148 7.912 52.008 ;
     RECT  7.912 2.418 8.104 52.008 ;
     RECT  8.104 40.128 8.201 48.792 ;
     RECT  8.201 40.128 8.243 46.104 ;
     RECT  8.243 40.128 8.435 40.248 ;
     RECT  8.243 41.328 8.435 46.104 ;
     RECT  8.104 50.016 8.531 52.008 ;
     RECT  8.201 47.136 8.533 48.792 ;
     RECT  7.693 53.04 8.557 53.064 ;
     RECT  8.531 50.304 8.561 52.008 ;
     RECT  8.435 41.472 8.597 46.104 ;
     RECT  8.561 51.312 8.629 52.008 ;
     RECT  8.557 53.04 8.629 53.88 ;
     RECT  8.597 46.08 8.633 46.104 ;
     RECT  8.104 5.04 8.705 8.424 ;
     RECT  8.597 41.472 8.705 45.048 ;
     RECT  8.705 41.472 8.741 43.608 ;
     RECT  8.561 50.304 8.813 50.328 ;
     RECT  8.629 51.312 8.963 53.88 ;
     RECT  8.963 51.792 9.155 53.88 ;
     RECT  9.097 2.688 9.209 2.712 ;
     RECT  9.155 53.856 9.251 53.88 ;
     RECT  8.705 5.232 9.385 8.424 ;
     RECT  8.104 9.648 9.385 9.672 ;
     RECT  8.533 47.136 9.425 47.4 ;
     RECT  8.741 41.472 9.457 43.32 ;
     RECT  7.189 0.096 9.484 0.12 ;
     RECT  9.155 51.792 9.605 52.776 ;
     RECT  8.705 44.592 9.637 45.048 ;
     RECT  9.457 41.376 9.817 43.32 ;
     RECT  9.385 5.232 9.925 9.672 ;
     RECT  9.637 44.592 9.997 45.24 ;
     RECT  8.533 48.672 10.177 48.792 ;
     RECT  10.177 47.712 10.261 48.792 ;
     RECT  9.817 50.496 10.261 50.52 ;
     RECT  10.261 47.712 10.307 51.672 ;
     RECT  10.307 47.712 10.348 50.088 ;
     RECT  9.925 5.232 10.429 10.056 ;
     RECT  10.357 46.704 10.469 46.728 ;
     RECT  10.465 0.528 10.537 0.552 ;
     RECT  9.817 41.184 10.645 43.32 ;
     RECT  9.997 44.496 10.645 45.24 ;
     RECT  10.537 0.528 10.717 1.176 ;
     RECT  10.453 2.304 10.717 2.328 ;
     RECT  10.393 39.312 10.717 39.336 ;
     RECT  10.645 41.184 10.753 45.24 ;
     RECT  10.753 41.136 10.789 45.24 ;
     RECT  9.605 52.704 10.789 52.776 ;
     RECT  10.789 40.992 10.861 45.24 ;
     RECT  10.429 4.896 10.897 10.056 ;
     RECT  10.897 4.896 10.933 10.152 ;
     RECT  10.717 38.976 10.933 39.336 ;
     RECT  10.933 3.408 11.029 3.432 ;
     RECT  10.933 4.896 11.029 10.872 ;
     RECT  11.029 3.408 11.113 10.872 ;
     RECT  10.307 51.36 11.149 51.672 ;
     RECT  10.789 52.704 11.149 52.824 ;
     RECT  11.113 3.408 11.189 11.208 ;
     RECT  10.348 47.808 11.225 50.088 ;
     RECT  10.717 0.528 11.437 2.328 ;
     RECT  10.933 53.856 11.459 53.88 ;
     RECT  11.225 47.808 11.477 49.56 ;
     RECT  10.933 38.928 11.545 39.336 ;
     RECT  11.477 48.432 11.555 49.56 ;
     RECT  11.149 51.36 11.605 52.824 ;
     RECT  11.545 38.736 11.617 39.336 ;
     RECT  11.605 51.312 11.617 52.824 ;
     RECT  11.437 0.528 11.651 2.904 ;
     RECT  8.104 22.176 11.725 22.2 ;
     RECT  11.189 3.984 11.797 11.208 ;
     RECT  11.797 3.984 11.804 11.352 ;
     RECT  11.804 3.984 11.845 12.024 ;
     RECT  11.845 3.984 11.891 12.6 ;
     RECT  11.651 0.528 11.893 2.328 ;
     RECT  11.893 0.096 11.945 2.328 ;
     RECT  11.617 51.312 12.035 53.064 ;
     RECT  11.617 38.448 12.049 39.336 ;
     RECT  10.861 40.992 12.301 45.336 ;
     RECT  11.945 0.096 12.449 1.848 ;
     RECT  11.905 47.376 12.481 47.4 ;
     RECT  11.555 48.432 12.481 48.84 ;
     RECT  12.229 50.112 12.481 50.136 ;
     RECT  12.035 51.312 12.481 52.824 ;
     RECT  12.049 38.4 12.985 39.336 ;
     RECT  12.449 1.152 13.021 1.848 ;
     RECT  11.891 3.984 13.093 11.4 ;
     RECT  13.021 1.152 13.105 1.896 ;
     RECT  13.093 3.456 13.208 11.4 ;
     RECT  11.891 12.576 13.208 12.6 ;
     RECT  11.725 22.032 13.208 22.2 ;
     RECT  8.104 27.696 13.208 27.72 ;
     RECT  8.104 36.864 13.208 36.888 ;
     RECT  12.985 38.4 13.208 39.816 ;
     RECT  12.301 40.992 13.208 45.528 ;
     RECT  12.481 47.376 13.208 48.84 ;
     RECT  12.481 50.112 13.208 52.824 ;
     RECT  13.208 2.148 13.312 52.824 ;
     RECT  13.105 1.152 13.385 1.176 ;
     RECT  12.449 0.096 13.429 0.168 ;
     RECT  13.312 2.418 13.504 52.824 ;
     RECT  13.429 0.096 13.619 0.216 ;
     RECT  13.504 3.984 13.637 11.208 ;
     RECT  13.619 0.096 13.667 0.168 ;
     RECT  13.504 22.032 13.667 22.2 ;
     RECT  13.637 8.736 13.673 11.208 ;
     RECT  13.504 47.376 13.709 50.376 ;
     RECT  13.673 8.784 13.745 11.208 ;
     RECT  13.637 3.984 13.781 7.656 ;
     RECT  13.745 8.784 13.925 11.16 ;
     RECT  13.667 0.144 13.997 0.168 ;
     RECT  13.504 39.792 14.069 39.816 ;
     RECT  13.504 38.16 14.105 38.76 ;
     RECT  13.709 47.376 14.357 49.608 ;
     RECT  14.357 47.664 14.501 49.608 ;
     RECT  14.173 53.856 14.531 53.88 ;
     RECT  14.581 1.152 14.677 1.176 ;
     RECT  14.677 1.152 14.681 1.752 ;
     RECT  14.681 1.728 14.713 1.752 ;
     RECT  14.485 2.88 14.713 2.904 ;
     RECT  13.504 51.456 14.773 52.824 ;
     RECT  13.504 36.864 14.821 36.888 ;
     RECT  14.713 1.728 14.869 2.904 ;
     RECT  13.781 4.08 14.869 7.656 ;
     RECT  14.869 1.728 15.073 7.656 ;
     RECT  13.925 8.784 15.073 11.016 ;
     RECT  14.105 38.256 15.073 38.76 ;
     RECT  15.073 38.256 15.077 39.48 ;
     RECT  14.821 36.864 15.437 36.984 ;
     RECT  15.073 1.728 15.581 11.016 ;
     RECT  15.077 38.4 15.721 39.48 ;
     RECT  14.773 50.688 15.761 52.824 ;
     RECT  14.501 48.432 15.781 49.608 ;
     RECT  15.761 51.216 15.827 52.824 ;
     RECT  15.437 36.864 15.829 36.888 ;
     RECT  15.829 36.432 15.869 36.888 ;
     RECT  15.781 48.432 16.189 50.088 ;
     RECT  13.504 41.376 16.225 45.528 ;
     RECT  15.937 46.56 16.225 46.584 ;
     RECT  15.721 38.4 16.261 39.816 ;
     RECT  15.869 36.432 16.301 36.6 ;
     RECT  16.261 38.16 16.301 39.816 ;
     RECT  15.581 1.728 16.337 3.432 ;
     RECT  16.189 47.616 16.549 50.088 ;
     RECT  16.301 38.16 16.589 38.664 ;
     RECT  16.225 41.376 16.621 46.584 ;
     RECT  16.549 47.568 16.621 50.088 ;
     RECT  16.301 39.792 16.693 39.816 ;
     RECT  16.621 41.376 16.693 50.088 ;
     RECT  16.337 1.728 16.765 2.376 ;
     RECT  16.301 36.576 16.841 36.6 ;
     RECT  16.765 1.152 16.849 2.376 ;
     RECT  15.827 51.216 16.909 51.672 ;
     RECT  16.337 3.408 17.017 3.432 ;
     RECT  15.581 4.896 17.017 11.016 ;
     RECT  16.693 39.792 17.021 50.088 ;
     RECT  17.021 39.792 17.057 46.344 ;
     RECT  17.021 47.856 17.057 50.088 ;
     RECT  17.057 48.24 17.089 50.088 ;
     RECT  16.909 51.12 17.089 51.672 ;
     RECT  17.057 39.792 17.093 46.248 ;
     RECT  16.849 1.584 17.123 2.376 ;
     RECT  17.089 48.24 17.365 51.672 ;
     RECT  15.827 52.704 17.365 52.824 ;
     RECT  17.017 3.408 17.452 11.016 ;
     RECT  17.452 3.984 17.453 11.016 ;
     RECT  16.589 38.16 17.461 38.52 ;
     RECT  17.453 3.984 17.525 10.632 ;
     RECT  17.093 39.792 17.561 46.056 ;
     RECT  17.461 37.632 17.989 38.52 ;
     RECT  17.365 48.24 18.169 52.824 ;
     RECT  17.449 34.896 18.205 34.92 ;
     RECT  18.197 53.856 18.241 53.88 ;
     RECT  17.989 37.632 18.277 38.76 ;
     RECT  18.241 53.856 18.28 53.976 ;
     RECT  18.277 37.632 18.38 38.808 ;
     RECT  17.561 39.792 18.38 43.368 ;
     RECT  18.28 53.808 18.389 53.976 ;
     RECT  18.205 34.896 18.421 35.16 ;
     RECT  18.38 37.632 18.529 43.368 ;
     RECT  17.123 1.728 18.569 2.376 ;
     RECT  18.569 1.872 18.605 2.376 ;
     RECT  18.605 2.148 18.608 2.376 ;
     RECT  17.525 4.896 18.608 10.632 ;
     RECT  13.667 22.08 18.608 22.2 ;
     RECT  13.504 27.696 18.608 27.72 ;
     RECT  18.284 33.648 18.608 33.672 ;
     RECT  18.421 34.752 18.608 35.16 ;
     RECT  17.377 36.144 18.608 36.456 ;
     RECT  18.529 37.44 18.608 43.368 ;
     RECT  17.561 44.592 18.608 46.056 ;
     RECT  18.169 47.28 18.608 52.824 ;
     RECT  18.608 2.148 18.904 52.824 ;
     RECT  18.904 4.512 18.965 10.44 ;
     RECT  16.981 0.096 19.429 0.12 ;
     RECT  18.904 2.148 19.469 2.328 ;
     RECT  19.429 0.096 19.613 0.6 ;
     RECT  19.613 0.576 19.619 0.6 ;
     RECT  19.609 1.728 19.715 1.752 ;
     RECT  18.904 22.176 19.933 22.536 ;
     RECT  18.904 34.752 19.937 36.456 ;
     RECT  19.933 22.176 19.973 22.776 ;
     RECT  19.973 22.512 20.017 22.776 ;
     RECT  18.965 4.656 20.081 10.44 ;
     RECT  20.081 10.176 20.153 10.44 ;
     RECT  20.081 4.656 20.189 9.048 ;
     RECT  18.904 48.24 20.243 52.824 ;
     RECT  18.904 44.592 20.401 45.96 ;
     RECT  18.904 47.184 20.401 47.208 ;
     RECT  20.243 48.24 20.401 48.696 ;
     RECT  20.189 4.656 20.441 9 ;
     RECT  20.441 4.704 20.549 9 ;
     RECT  19.937 34.944 20.581 36.456 ;
     RECT  18.904 37.44 20.581 43.608 ;
     RECT  18.389 53.904 20.581 53.976 ;
     RECT  20.549 4.704 20.585 8.808 ;
     RECT  20.545 32.4 20.653 32.424 ;
     RECT  20.653 32.4 20.654 32.472 ;
     RECT  20.585 4.704 20.657 7.656 ;
     RECT  20.221 33.6 20.689 33.624 ;
     RECT  20.689 33.6 20.729 33.864 ;
     RECT  20.243 50.016 20.761 52.824 ;
     RECT  20.581 53.808 20.761 53.976 ;
     RECT  20.761 50.016 20.771 53.976 ;
     RECT  20.717 1.728 20.801 1.752 ;
     RECT  20.729 33.84 20.819 33.864 ;
     RECT  20.654 32.448 20.867 32.472 ;
     RECT  20.657 4.752 20.945 7.656 ;
     RECT  20.581 34.944 21.049 43.608 ;
     RECT  20.401 44.592 21.049 48.696 ;
     RECT  20.153 10.176 21.125 10.2 ;
     RECT  21.049 34.944 21.193 48.696 ;
     RECT  20.771 52.8 21.449 53.976 ;
     RECT  21.193 34.752 21.557 48.696 ;
     RECT  20.585 8.736 21.809 8.808 ;
     RECT  20.771 50.016 21.913 51.768 ;
     RECT  21.449 52.8 21.913 53.88 ;
     RECT  21.841 1.728 21.925 1.752 ;
     RECT  21.557 34.8 21.989 48.696 ;
     RECT  20.945 4.752 22.165 7.608 ;
     RECT  21.989 35.856 22.201 48.696 ;
     RECT  21.913 50.016 22.201 53.88 ;
     RECT  22.165 4.752 22.205 7.944 ;
     RECT  21.989 34.8 22.597 34.824 ;
     RECT  22.597 34.176 22.681 34.824 ;
     RECT  22.201 35.856 22.745 53.88 ;
     RECT  22.745 35.856 22.853 41.544 ;
     RECT  21.769 0.576 22.979 0.6 ;
     RECT  22.745 42.528 23.141 53.88 ;
     RECT  22.205 4.896 23.317 7.944 ;
     RECT  23.245 9.12 23.317 9.144 ;
     RECT  22.853 35.856 23.821 41.448 ;
     RECT  23.141 42.528 23.821 53.64 ;
     RECT  23.317 4.896 24.008 9.144 ;
     RECT  20.017 22.512 24.008 22.536 ;
     RECT  18.904 27.696 24.008 27.72 ;
     RECT  23.677 31.872 24.008 31.896 ;
     RECT  22.381 33.024 24.008 33.048 ;
     RECT  22.681 34.752 24.008 34.824 ;
     RECT  23.821 35.856 24.008 53.64 ;
     RECT  24.008 2.148 24.112 53.64 ;
     RECT  24.112 2.418 24.227 53.64 ;
     RECT  24.227 2.418 24.304 52.536 ;
     RECT  24.304 5.472 24.401 7.176 ;
     RECT  24.304 36.48 24.515 52.536 ;
     RECT  24.227 53.616 24.565 53.64 ;
     RECT  24.304 27.696 24.725 28.056 ;
     RECT  24.401 5.472 24.905 6.36 ;
     RECT  24.515 36.48 25.049 50.184 ;
     RECT  24.304 22.512 25.091 22.536 ;
     RECT  24.725 28.032 25.265 28.056 ;
     RECT  25.049 36.48 25.292 44.184 ;
     RECT  24.304 32.064 25.331 32.088 ;
     RECT  25.297 33.6 25.333 33.624 ;
     RECT  25.292 35.52 25.379 44.184 ;
     RECT  24.515 51.312 25.379 52.536 ;
     RECT  25.333 33.6 25.381 34.392 ;
     RECT  24.905 5.472 25.445 5.496 ;
     RECT  25.379 51.792 25.475 52.536 ;
     RECT  25.475 52.464 25.484 52.536 ;
     RECT  24.565 53.616 25.484 53.88 ;
     RECT  25.484 52.464 25.571 53.88 ;
     RECT  25.379 36.48 25.625 44.184 ;
     RECT  25.049 45.168 25.661 50.184 ;
     RECT  25.381 34.176 25.765 34.392 ;
     RECT  25.625 36.48 25.913 40.968 ;
     RECT  25.625 42.528 26.233 44.184 ;
     RECT  25.661 45.168 26.233 50.136 ;
     RECT  25.913 39.648 26.237 40.968 ;
     RECT  25.571 53.616 26.243 53.88 ;
     RECT  25.765 34.176 26.345 34.824 ;
     RECT  26.444 51.312 26.531 51.336 ;
     RECT  26.237 39.648 26.597 40.872 ;
     RECT  26.233 42.528 26.597 50.136 ;
     RECT  26.597 42.528 26.737 49.08 ;
     RECT  25.913 36.48 26.953 38.664 ;
     RECT  26.597 39.648 26.953 40.632 ;
     RECT  26.345 34.176 27.277 34.392 ;
     RECT  27.349 35.424 27.436 35.448 ;
     RECT  25.571 52.464 27.541 52.488 ;
     RECT  26.243 53.856 27.541 53.88 ;
     RECT  26.737 42 27.673 49.08 ;
     RECT  26.597 50.112 27.673 50.136 ;
     RECT  26.953 36.48 27.709 40.632 ;
     RECT  27.673 42 27.709 50.136 ;
     RECT  27.541 52.464 27.713 53.88 ;
     RECT  27.709 36.48 27.749 50.136 ;
     RECT  27.277 33.792 27.929 34.392 ;
     RECT  27.829 51.312 27.929 51.336 ;
     RECT  27.749 36.48 27.965 41.496 ;
     RECT  27.713 53.856 28.001 53.88 ;
     RECT  27.929 33.792 28.217 34.2 ;
     RECT  27.965 36.48 28.393 40.392 ;
     RECT  28.393 35.808 28.433 40.392 ;
     RECT  27.713 52.464 28.681 52.488 ;
     RECT  28.825 51.408 28.988 51.432 ;
     RECT  28.681 52.464 29.08 52.968 ;
     RECT  27.749 42.672 29.221 50.136 ;
     RECT  28.988 51.312 29.221 51.432 ;
     RECT  29.08 52.464 29.221 53.064 ;
     RECT  29.221 42.672 29.293 51.432 ;
     RECT  29.221 52.464 29.293 53.832 ;
     RECT  29.293 42.672 29.329 53.832 ;
     RECT  28.433 35.808 29.408 39.864 ;
     RECT  27.965 41.472 29.408 41.496 ;
     RECT  29.329 42.576 29.408 53.832 ;
     RECT  29.408 2.148 29.512 53.832 ;
     RECT  29.512 2.418 29.704 53.832 ;
     RECT  29.704 40.944 29.761 53.832 ;
     RECT  29.761 40.944 29.795 53.88 ;
     RECT  29.795 53.04 30.179 53.88 ;
     RECT  29.704 36.24 30.197 39.768 ;
     RECT  29.795 40.944 30.305 51.864 ;
     RECT  30.305 40.944 30.341 50.184 ;
     RECT  30.341 41.136 30.659 50.184 ;
     RECT  30.659 41.136 30.809 50.136 ;
     RECT  30.179 53.04 30.851 53.064 ;
     RECT  30.809 41.136 30.881 42.12 ;
     RECT  30.197 36.528 30.917 39.768 ;
     RECT  30.917 36.528 31.133 38.184 ;
     RECT  30.881 41.808 31.277 42.12 ;
     RECT  30.809 43.104 31.277 50.136 ;
     RECT  31.373 53.856 31.957 53.88 ;
     RECT  30.305 51.312 32.029 51.864 ;
     RECT  31.957 53.808 32.156 53.88 ;
     RECT  31.277 43.104 32.185 50.088 ;
     RECT  31.277 41.808 32.213 41.976 ;
     RECT  32.156 53.76 32.213 53.88 ;
     RECT  32.213 53.76 32.243 53.832 ;
     RECT  32.213 41.856 32.317 41.976 ;
     RECT  32.185 43.104 32.317 49.704 ;
     RECT  32.243 53.808 32.435 53.832 ;
     RECT  30.917 39.216 32.485 39.768 ;
     RECT  32.317 40.848 32.485 40.872 ;
     RECT  31.133 36.816 32.893 38.184 ;
     RECT  32.485 39.216 32.893 40.872 ;
     RECT  32.029 51.312 33.101 51.912 ;
     RECT  32.317 41.856 33.245 49.704 ;
     RECT  33.101 50.736 33.245 51.912 ;
     RECT  32.893 36.816 33.469 40.872 ;
     RECT  33.245 41.856 33.469 51.912 ;
     RECT  33.445 52.992 33.635 53.016 ;
     RECT  33.469 36.816 33.781 51.912 ;
     RECT  33.781 36.816 34.261 51.96 ;
     RECT  34.261 36 34.808 51.96 ;
     RECT  34.808 2.148 34.837 51.96 ;
     RECT  34.837 2.148 34.912 52.008 ;
     RECT  34.597 53.808 34.933 53.832 ;
     RECT  34.912 2.418 35.029 52.008 ;
     RECT  35.029 2.418 35.104 52.488 ;
     RECT  34.933 53.616 35.125 53.832 ;
     RECT  35.104 39.216 35.173 52.488 ;
     RECT  35.125 53.52 35.173 53.832 ;
     RECT  35.173 39.216 35.315 53.832 ;
     RECT  35.315 39.264 35.317 53.832 ;
     RECT  35.317 39.264 35.489 53.88 ;
     RECT  35.489 40.32 35.705 53.88 ;
     RECT  35.705 41.904 35.747 53.88 ;
     RECT  35.104 36 35.813 37.896 ;
     RECT  35.747 41.904 35.843 53.832 ;
     RECT  35.843 41.904 35.849 53.016 ;
     RECT  35.849 41.904 35.921 49.608 ;
     RECT  35.705 40.32 36.029 40.344 ;
     RECT  35.489 39.264 36.137 39.288 ;
     RECT  35.849 50.688 36.461 53.016 ;
     RECT  36.461 52.464 36.497 53.016 ;
     RECT  35.921 41.904 36.533 49.512 ;
     RECT  36.533 43.344 36.605 49.512 ;
     RECT  36.605 43.872 36.749 49.512 ;
     RECT  36.497 52.992 36.755 53.016 ;
     RECT  36.533 41.904 36.947 41.928 ;
     RECT  35.813 36.816 36.997 37.896 ;
     RECT  36.749 43.872 37.001 49.464 ;
     RECT  37.001 43.872 37.073 43.896 ;
     RECT  36.997 36.816 37.141 38.136 ;
     RECT  37.033 39.216 37.141 39.24 ;
     RECT  37.141 36.816 37.217 39.24 ;
     RECT  37.001 44.928 37.253 49.464 ;
     RECT  37.253 45.792 37.577 49.464 ;
     RECT  36.461 50.688 37.609 51.288 ;
     RECT  37.217 36.816 37.613 37.128 ;
     RECT  37.217 38.112 37.757 39.24 ;
     RECT  37.609 50.688 37.757 51.864 ;
     RECT  37.501 53.856 37.763 53.88 ;
     RECT  37.724 40.56 37.811 40.584 ;
     RECT  37.577 48.768 37.865 49.464 ;
     RECT  37.757 51.696 37.996 51.864 ;
     RECT  37.577 45.792 38.045 47.592 ;
     RECT  38.045 45.792 38.081 46.392 ;
     RECT  37.996 51.696 38.153 51.816 ;
     RECT  38.153 51.792 38.189 51.816 ;
     RECT  37.757 50.688 38.225 50.712 ;
     RECT  38.081 46.176 38.261 46.392 ;
     RECT  38.261 46.176 38.294 46.248 ;
     RECT  37.757 38.688 38.297 39.24 ;
     RECT  38.045 47.568 38.773 47.592 ;
     RECT  37.865 48.768 38.773 48.84 ;
     RECT  38.773 47.568 38.819 48.84 ;
     RECT  38.797 41.376 39.013 41.4 ;
     RECT  39.013 41.04 39.161 41.4 ;
     RECT  39.149 51.84 39.233 51.864 ;
     RECT  38.294 46.176 39.373 46.2 ;
     RECT  38.297 38.688 39.445 38.712 ;
     RECT  39.373 45.456 39.877 46.2 ;
     RECT  39.877 45.456 39.925 46.68 ;
     RECT  39.973 50.112 40.069 50.136 ;
     RECT  39.973 53.856 40.069 53.88 ;
     RECT  39.925 45.456 40.165 46.776 ;
     RECT  37.613 37.104 40.208 37.128 ;
     RECT  39.445 38.688 40.208 39.336 ;
     RECT  39.161 41.376 40.208 41.4 ;
     RECT  40.165 44.64 40.208 46.776 ;
     RECT  38.819 47.856 40.208 48.84 ;
     RECT  40.069 50.016 40.208 50.136 ;
     RECT  40.069 53.808 40.259 53.88 ;
     RECT  40.208 2.148 40.312 51.852 ;
     RECT  40.312 2.418 40.345 51.852 ;
     RECT  40.259 53.808 40.355 53.832 ;
     RECT  40.345 2.418 40.504 52.488 ;
     RECT  40.504 51.84 40.561 52.488 ;
     RECT  40.504 42.672 40.925 48.744 ;
     RECT  40.925 45.408 41.033 48.744 ;
     RECT  40.561 51.84 41.033 53.016 ;
     RECT  40.504 50.592 41.041 50.712 ;
     RECT  40.504 40.464 41.141 41.4 ;
     RECT  41.033 52.368 41.329 53.016 ;
     RECT  41.033 45.408 41.357 47.88 ;
     RECT  41.329 52.416 41.393 53.016 ;
     RECT  40.504 39.312 41.465 39.336 ;
     RECT  41.357 45.696 41.537 47.832 ;
     RECT  41.393 52.416 41.537 52.44 ;
     RECT  41.141 40.464 41.789 40.488 ;
     RECT  40.925 42.672 42.077 44.424 ;
     RECT  41.641 48.912 42.113 48.936 ;
     RECT  42.14 42.144 42.227 42.168 ;
     RECT  41.537 47.136 42.361 47.832 ;
     RECT  42.077 43.68 42.473 44.424 ;
     RECT  41.537 45.696 42.505 46.056 ;
     RECT  42.361 47.136 42.505 48.744 ;
     RECT  41.041 50.688 42.517 50.712 ;
     RECT  42.517 50.16 42.689 50.712 ;
     RECT  40.504 37.104 42.761 37.128 ;
     RECT  42.613 53.04 42.805 53.064 ;
     RECT  42.805 52.416 43.049 53.064 ;
     RECT  43.049 52.416 43.189 52.44 ;
     RECT  42.473 44.16 43.297 44.424 ;
     RECT  42.505 45.696 43.373 48.744 ;
     RECT  43.373 48.192 43.409 48.744 ;
     RECT  42.689 50.448 43.513 50.712 ;
     RECT  43.189 51.84 43.513 52.44 ;
     RECT  43.409 48.336 43.769 48.744 ;
     RECT  43.513 50.448 43.805 52.44 ;
     RECT  43.805 52.416 43.841 52.44 ;
     RECT  43.769 48.72 43.873 48.744 ;
     RECT  43.805 50.448 43.907 51.336 ;
     RECT  43.873 48.72 43.913 48.984 ;
     RECT  43.297 44.16 43.981 44.472 ;
     RECT  43.093 53.856 44.381 53.88 ;
     RECT  43.981 43.536 44.413 44.472 ;
     RECT  43.373 45.696 44.413 47.208 ;
     RECT  44.413 43.536 44.453 47.208 ;
     RECT  43.907 50.448 44.525 50.712 ;
     RECT  44.453 44.4 44.665 47.208 ;
     RECT  44.665 44.4 44.953 47.736 ;
     RECT  43.913 48.96 44.953 48.984 ;
     RECT  45.013 52.992 45.173 53.016 ;
     RECT  44.953 44.4 45.608 48.984 ;
     RECT  44.525 50.688 45.608 50.712 ;
     RECT  45.608 2.148 45.712 51.852 ;
     RECT  45.712 2.418 45.904 51.852 ;
     RECT  45.904 51.84 46.061 51.852 ;
     RECT  46.061 51.84 46.145 51.864 ;
     RECT  45.904 44.88 46.253 45 ;
     RECT  46.253 44.88 46.325 44.904 ;
     RECT  45.904 46.56 46.325 46.584 ;
     RECT  51.008 2.148 51.112 51.852 ;
     RECT  51.112 2.418 51.304 51.582 ;
     RECT  56.408 2.148 56.512 51.852 ;
     RECT  56.512 2.418 56.704 51.582 ;
     RECT  61.808 2.148 61.912 51.852 ;
     RECT  61.912 2.418 62.104 51.582 ;
     RECT  67.208 2.148 67.312 51.852 ;
     RECT  67.312 2.418 67.504 51.582 ;
     RECT  72.608 2.148 72.712 51.852 ;
     RECT  72.712 2.418 72.904 51.582 ;
     RECT  78.008 2.148 78.112 51.852 ;
     RECT  78.112 2.418 78.304 51.582 ;
     RECT  83.408 2.148 83.512 51.852 ;
     RECT  83.512 2.418 83.704 51.582 ;
    LAYER M5 ;
     RECT  10.464 0.016 13.464 0.085 ;
     RECT  14.496 0.016 17.496 0.085 ;
     RECT  9.312 0.016 9.432 0.131 ;
     RECT  19.584 0.016 19.704 0.611 ;
     RECT  21.792 0.016 21.912 0.611 ;
     RECT  19.68 0.611 19.704 1.763 ;
     RECT  21.888 0.611 21.912 1.763 ;
     RECT  10.464 0.085 17.496 2.003 ;
     RECT  2.4 2.137 2.52 2.151 ;
     RECT  7.8 2.137 7.92 2.151 ;
     RECT  24 2.137 24.12 2.151 ;
     RECT  29.4 2.137 29.52 2.151 ;
     RECT  34.8 2.137 34.92 2.151 ;
     RECT  40.2 2.137 40.32 2.151 ;
     RECT  45.6 2.137 45.72 2.151 ;
     RECT  51 2.137 51.12 2.151 ;
     RECT  56.4 2.137 56.52 2.151 ;
     RECT  61.8 2.137 61.92 2.151 ;
     RECT  67.2 2.137 67.32 2.151 ;
     RECT  72.6 2.137 72.72 2.151 ;
     RECT  78 2.137 78.12 2.151 ;
     RECT  83.4 2.137 83.52 2.151 ;
     RECT  10.464 2.003 16.152 2.339 ;
     RECT  17.184 2.003 17.496 2.339 ;
     RECT  10.944 2.339 16.152 2.915 ;
     RECT  17.376 2.339 17.496 3.397 ;
     RECT  10.944 2.915 13.656 3.443 ;
     RECT  14.88 2.915 15.384 3.683 ;
     RECT  15.072 3.683 15.384 3.827 ;
     RECT  11.04 3.443 13.656 4.019 ;
     RECT  15.072 3.827 15.288 4.019 ;
     RECT  17.28 3.397 17.496 4.019 ;
     RECT  12.96 4.019 13.608 4.115 ;
     RECT  15.072 4.019 15.096 4.547 ;
     RECT  24 2.151 24.312 5.029 ;
     RECT  12.96 4.115 13.512 5.171 ;
     RECT  17.28 4.019 17.304 5.461 ;
     RECT  18.6 2.137 18.912 5.461 ;
     RECT  17.088 5.461 18.912 5.651 ;
     RECT  14.832 5.029 14.856 5.653 ;
     RECT  14.832 5.653 15.336 5.747 ;
     RECT  13.104 5.171 13.512 5.797 ;
     RECT  13.104 5.797 13.608 5.843 ;
     RECT  17.28 5.651 18.912 6.275 ;
     RECT  15.312 5.747 15.336 6.419 ;
     RECT  23.184 5.029 24.312 6.805 ;
     RECT  23.04 6.805 24.312 7.811 ;
     RECT  17.28 6.275 17.304 9.251 ;
     RECT  9.936 9.013 9.96 10.067 ;
     RECT  13.2 5.843 13.608 10.885 ;
     RECT  13.104 10.885 13.608 10.931 ;
     RECT  11.856 10.837 11.88 12.611 ;
     RECT  13.104 10.931 13.512 22.021 ;
     RECT  13.104 22.021 13.656 22.067 ;
     RECT  18.6 6.275 18.912 22.069 ;
     RECT  4.224 5.029 4.248 22.211 ;
     RECT  13.2 22.067 13.656 22.211 ;
     RECT  23.184 7.811 24.312 22.501 ;
     RECT  0.192 4.021 0.216 27.731 ;
     RECT  23.184 22.501 25.08 32.053 ;
     RECT  19.968 22.741 19.992 32.389 ;
     RECT  19.968 32.389 20.616 32.437 ;
     RECT  23.184 32.053 25.32 33.013 ;
     RECT  22.416 33.013 25.32 33.589 ;
     RECT  18.336 22.069 18.912 33.683 ;
     RECT  22.416 33.589 25.368 34.549 ;
     RECT  22.416 34.549 26.136 34.787 ;
     RECT  34.8 2.151 35.112 35.989 ;
     RECT  18.6 33.683 18.912 36.325 ;
     RECT  27.36 34.357 27.384 36.515 ;
     RECT  29.4 2.151 29.712 36.517 ;
     RECT  29.4 36.517 29.928 36.659 ;
     RECT  7.8 2.151 8.112 36.853 ;
     RECT  22.416 34.787 25.368 37.091 ;
     RECT  22.416 37.091 25.32 37.235 ;
     RECT  34.8 35.989 35.208 37.573 ;
     RECT  18.24 36.325 18.912 37.621 ;
     RECT  17.472 37.621 18.912 37.667 ;
     RECT  19.968 32.437 20.856 37.667 ;
     RECT  17.472 37.667 17.496 38.965 ;
     RECT  18.6 37.667 18.912 38.965 ;
     RECT  17.472 38.965 18.912 39.107 ;
     RECT  7.8 36.853 8.424 39.829 ;
     RECT  33.648 38.053 33.672 40.019 ;
     RECT  37.776 38.677 37.8 40.595 ;
     RECT  17.472 39.107 17.496 41.075 ;
     RECT  34.8 37.573 35.304 41.845 ;
     RECT  32.496 40.453 32.52 41.941 ;
     RECT  32.496 41.941 33.096 42.227 ;
     RECT  6.816 39.829 8.424 42.229 ;
     RECT  34.8 41.845 35.4 42.515 ;
     RECT  40.2 2.151 40.512 42.757 ;
     RECT  4.032 37.189 4.056 43.285 ;
     RECT  33.072 42.227 33.096 43.331 ;
     RECT  40.2 42.757 41.16 43.379 ;
     RECT  6.816 42.229 8.568 43.523 ;
     RECT  7.8 43.523 8.568 43.619 ;
     RECT  4.032 43.285 4.296 44.099 ;
     RECT  36.912 41.893 36.936 44.869 ;
     RECT  34.8 42.515 35.304 44.917 ;
     RECT  36.336 44.869 36.936 44.917 ;
     RECT  20.208 37.667 20.856 45.013 ;
     RECT  18.6 39.107 18.912 45.109 ;
     RECT  18 45.109 18.912 45.251 ;
     RECT  33.12 44.389 33.384 45.301 ;
     RECT  20.208 45.013 21.336 45.445 ;
     RECT  22.416 37.235 24.312 45.445 ;
     RECT  7.8 43.619 8.232 45.493 ;
     RECT  33.024 45.301 33.384 45.541 ;
     RECT  34.8 44.917 36.936 45.541 ;
     RECT  5.376 39.781 5.4 45.637 ;
     RECT  28.08 36.997 28.104 45.637 ;
     RECT  29.4 36.659 29.712 45.637 ;
     RECT  5.136 45.637 5.4 45.683 ;
     RECT  17.04 46.021 17.064 46.163 ;
     RECT  42.192 42.133 42.216 46.165 ;
     RECT  28.08 45.637 29.712 46.211 ;
     RECT  40.2 43.379 40.512 46.645 ;
     RECT  42.192 46.165 43.128 46.739 ;
     RECT  20.208 45.445 24.312 46.741 ;
     RECT  25.296 37.235 25.32 46.741 ;
     RECT  5.136 45.683 5.16 46.787 ;
     RECT  20.208 46.741 25.32 46.787 ;
     RECT  39.936 46.645 40.512 46.787 ;
     RECT  37.92 45.829 37.944 47.027 ;
     RECT  4.032 44.099 4.056 47.221 ;
     RECT  22.416 46.787 25.32 47.269 ;
     RECT  29.4 46.211 29.712 47.317 ;
     RECT  28.08 46.211 28.104 47.459 ;
     RECT  29.136 47.317 29.712 47.461 ;
     RECT  29.088 47.461 29.712 47.651 ;
     RECT  22.416 47.269 25.656 47.843 ;
     RECT  42.192 46.739 42.216 47.843 ;
     RECT  7.8 45.493 8.28 47.845 ;
     RECT  32.832 45.541 36.936 47.845 ;
     RECT  3.744 47.221 4.056 47.891 ;
     RECT  5.664 47.269 5.688 47.891 ;
     RECT  29.136 47.651 29.712 47.891 ;
     RECT  38.784 47.557 38.808 47.891 ;
     RECT  31.68 47.845 31.704 47.893 ;
     RECT  32.736 47.845 36.936 47.893 ;
     RECT  31.68 47.893 36.936 47.939 ;
     RECT  29.184 47.891 29.712 48.037 ;
     RECT  20.208 46.787 21.144 48.227 ;
     RECT  18.6 45.251 18.912 48.229 ;
     RECT  31.68 47.939 36.744 48.421 ;
     RECT  29.184 48.037 29.832 48.757 ;
     RECT  25.296 47.843 25.656 48.803 ;
     RECT  29.184 48.757 30.216 48.997 ;
     RECT  26.784 47.413 26.808 49.091 ;
     RECT  31.536 48.421 36.744 49.189 ;
     RECT  18.48 48.229 18.912 49.331 ;
     RECT  6.72 45.973 6.744 49.333 ;
     RECT  7.8 47.845 8.52 49.333 ;
     RECT  29.088 48.997 30.216 49.525 ;
     RECT  31.488 49.189 36.744 49.525 ;
     RECT  40.2 46.787 40.512 50.005 ;
     RECT  6.72 49.333 8.52 50.051 ;
     RECT  29.088 49.525 36.744 50.053 ;
     RECT  2.4 2.151 2.712 50.101 ;
     RECT  20.208 48.227 20.856 50.101 ;
     RECT  40.08 50.005 40.512 50.101 ;
     RECT  42.528 50.149 42.552 50.437 ;
     RECT  39.984 50.101 40.512 50.581 ;
     RECT  39.984 50.581 41.016 50.677 ;
     RECT  42.528 50.437 43.416 50.677 ;
     RECT  22.416 47.843 24.312 50.725 ;
     RECT  2.4 50.101 2.808 50.867 ;
     RECT  20.064 50.101 20.856 50.963 ;
     RECT  22.272 50.725 24.312 51.109 ;
     RECT  25.296 48.803 25.32 51.109 ;
     RECT  6.72 50.051 8.376 51.301 ;
     RECT  11.52 49.525 11.544 51.301 ;
     RECT  13.2 22.211 13.512 51.301 ;
     RECT  14.784 50.677 14.808 51.301 ;
     RECT  15.792 50.053 15.816 51.301 ;
     RECT  22.272 51.109 25.32 51.301 ;
     RECT  42.528 50.677 43.8 51.301 ;
     RECT  20.544 50.963 20.856 51.347 ;
     RECT  29.04 50.053 36.744 51.347 ;
     RECT  18.6 49.331 18.912 51.349 ;
     RECT  10.272 47.701 10.296 51.395 ;
     RECT  20.592 51.347 20.856 51.493 ;
     RECT  22.176 51.301 25.368 51.493 ;
     RECT  17.76 51.349 18.912 51.637 ;
     RECT  14.784 51.301 15.816 51.779 ;
     RECT  5.088 51.301 5.4 51.781 ;
     RECT  6.72 51.301 8.952 51.781 ;
     RECT  11.52 51.301 13.512 51.781 ;
     RECT  14.784 51.779 15.576 51.781 ;
     RECT  20.592 51.493 25.368 51.781 ;
     RECT  38.112 51.685 38.136 51.781 ;
     RECT  11.328 51.781 15.576 51.829 ;
     RECT  17.472 51.637 18.912 51.829 ;
     RECT  38.016 51.781 38.136 51.829 ;
     RECT  39.984 50.677 41.4 51.829 ;
     RECT  45.6 2.151 45.912 51.829 ;
     RECT  2.4 50.867 2.712 51.849 ;
     RECT  11.232 51.829 15.576 51.849 ;
     RECT  17.376 51.829 18.912 51.849 ;
     RECT  51 2.151 51.312 51.849 ;
     RECT  56.4 2.151 56.712 51.849 ;
     RECT  61.8 2.151 62.112 51.849 ;
     RECT  67.2 2.151 67.512 51.849 ;
     RECT  72.6 2.151 72.912 51.849 ;
     RECT  78 2.151 78.312 51.849 ;
     RECT  83.4 2.151 83.712 51.849 ;
     RECT  2.4 51.849 2.52 51.863 ;
     RECT  5.088 51.781 9.432 51.863 ;
     RECT  11.232 51.849 13.32 51.863 ;
     RECT  17.376 51.849 18.72 51.863 ;
     RECT  45.6 51.829 46.104 51.863 ;
     RECT  51 51.849 51.12 51.863 ;
     RECT  56.4 51.849 56.52 51.863 ;
     RECT  61.8 51.849 61.92 51.863 ;
     RECT  67.2 51.849 67.32 51.863 ;
     RECT  72.6 51.849 72.72 51.863 ;
     RECT  78 51.849 78.12 51.863 ;
     RECT  83.4 51.849 83.52 51.863 ;
     RECT  39.168 51.829 41.4 52.405 ;
     RECT  20.592 51.781 25.464 52.453 ;
     RECT  26.496 51.301 26.52 52.453 ;
     RECT  27.84 51.301 27.864 52.453 ;
     RECT  29.088 51.347 36.744 52.549 ;
     RECT  20.592 52.453 26.52 52.693 ;
     RECT  27.648 52.453 27.864 52.981 ;
     RECT  28.992 52.549 36.744 53.027 ;
     RECT  27.552 52.981 27.864 53.845 ;
     RECT  37.824 51.829 38.136 53.845 ;
     RECT  42.528 51.301 43.896 53.845 ;
     RECT  28.992 53.027 36.696 53.891 ;
     RECT  39.168 52.405 41.496 53.891 ;
     RECT  5.088 51.863 6.84 53.968 ;
     RECT  8.16 51.863 9.432 53.968 ;
     RECT  11.232 51.863 12.504 53.968 ;
     RECT  14.304 51.849 15.576 53.968 ;
     RECT  17.376 51.863 18.648 53.968 ;
     RECT  20.448 52.693 26.52 53.968 ;
     RECT  27.552 53.845 27.96 53.968 ;
     RECT  28.992 53.891 35.64 53.968 ;
     RECT  37.728 53.845 38.136 53.968 ;
     RECT  40.224 53.891 41.496 53.968 ;
     RECT  42.528 53.845 43.992 53.968 ;
     RECT  9.48 0.016 10.416 0.131 ;
     RECT  13.512 0.016 14.448 0.085 ;
     RECT  16.152 2.003 17.184 2.339 ;
     RECT  17.496 2.137 18.6 4.019 ;
     RECT  16.152 2.339 17.376 2.915 ;
     RECT  13.656 2.915 14.88 3.683 ;
     RECT  17.28 2.915 17.376 3.397 ;
     RECT  13.656 3.683 15.072 4.019 ;
     RECT  13.608 4.019 15.072 4.115 ;
     RECT  17.304 4.019 18.6 5.461 ;
     RECT  13.512 4.115 15.072 4.547 ;
     RECT  13.512 4.547 15.096 5.029 ;
     RECT  2.712 5.029 4.224 22.211 ;
     RECT  13.512 5.029 14.832 5.747 ;
     RECT  14.856 5.029 15.096 5.653 ;
     RECT  13.512 5.747 13.608 5.797 ;
     RECT  17.304 6.275 18.6 9.251 ;
     RECT  11.88 10.837 13.2 10.885 ;
     RECT  11.88 10.885 13.104 12.611 ;
     RECT  18.912 22.741 19.968 37.667 ;
     RECT  26.136 34.549 27.36 34.787 ;
     RECT  28.104 36.997 29.4 45.637 ;
     RECT  2.712 37.189 4.032 47.221 ;
     RECT  24.312 37.235 25.296 46.741 ;
     RECT  17.496 37.667 18.6 38.965 ;
     RECT  18.912 37.667 20.208 50.101 ;
     RECT  33.672 38.053 34.8 40.019 ;
     RECT  17.496 39.107 18.6 41.075 ;
     RECT  4.056 39.781 5.376 43.285 ;
     RECT  5.4 39.829 6.816 43.523 ;
     RECT  35.4 41.893 36.912 42.515 ;
     RECT  41.16 42.757 42.192 43.379 ;
     RECT  4.296 43.285 5.376 44.099 ;
     RECT  4.056 44.099 5.376 45.637 ;
     RECT  33.384 44.389 34.8 45.541 ;
     RECT  35.304 44.869 36.336 44.917 ;
     RECT  21.336 45.013 22.416 45.445 ;
     RECT  4.056 45.637 5.136 46.787 ;
     RECT  36.936 45.829 37.92 47.027 ;
     RECT  6.744 45.973 7.8 49.333 ;
     RECT  28.104 46.211 29.4 47.317 ;
     RECT  21.144 46.787 22.416 48.227 ;
     RECT  39.936 46.787 40.2 47.557 ;
     RECT  2.712 47.221 3.744 47.891 ;
     RECT  5.688 47.269 6.72 47.891 ;
     RECT  28.104 47.317 29.136 47.459 ;
     RECT  25.656 47.413 26.784 48.803 ;
     RECT  26.808 47.413 28.08 47.459 ;
     RECT  29.088 47.459 29.136 47.461 ;
     RECT  38.808 47.557 40.2 47.891 ;
     RECT  29.088 47.651 29.136 47.891 ;
     RECT  24.312 47.843 25.296 51.109 ;
     RECT  31.704 47.845 32.736 47.893 ;
     RECT  29.088 47.891 29.184 48.997 ;
     RECT  30.216 48.757 31.536 49.189 ;
     RECT  25.32 48.803 26.784 49.091 ;
     RECT  30.216 49.189 31.488 49.525 ;
     RECT  10.296 49.525 11.52 51.395 ;
     RECT  8.376 50.051 8.52 51.301 ;
     RECT  18.912 50.101 20.064 50.963 ;
     RECT  41.016 50.581 42.528 50.677 ;
     RECT  13.512 50.677 14.784 51.781 ;
     RECT  14.808 50.677 15.792 51.301 ;
     RECT  41.4 50.677 42.528 52.405 ;
     RECT  20.856 50.725 22.272 51.301 ;
     RECT  5.4 51.301 6.72 51.781 ;
     RECT  8.952 51.301 10.272 51.395 ;
     RECT  20.856 51.301 22.176 51.493 ;
     RECT  25.368 51.301 26.496 51.781 ;
     RECT  26.52 51.301 27.84 52.453 ;
     RECT  27.864 51.301 29.04 51.347 ;
     RECT  20.544 51.347 20.592 52.693 ;
     RECT  27.864 51.347 29.088 52.549 ;
     RECT  8.952 51.395 9.432 51.781 ;
     RECT  11.232 51.395 11.52 51.781 ;
     RECT  36.744 51.685 38.112 51.781 ;
     RECT  11.232 51.781 11.328 51.829 ;
     RECT  25.464 51.781 26.496 52.453 ;
     RECT  36.744 51.781 38.016 51.829 ;
     RECT  36.744 51.829 37.824 53.027 ;
     RECT  38.136 51.829 39.168 53.843 ;
     RECT  13.32 51.849 14.304 51.863 ;
     RECT  6.84 51.863 8.16 53.868 ;
     RECT  41.496 52.405 42.528 53.868 ;
     RECT  26.52 52.453 27.648 52.981 ;
     RECT  27.864 52.549 28.992 53.845 ;
     RECT  26.52 52.981 27.552 53.868 ;
     RECT  36.696 53.027 37.824 53.843 ;
     RECT  36.744 53.843 37.824 53.845 ;
     RECT  38.136 53.843 39.12 53.868 ;
     RECT  27.96 53.845 28.992 53.868 ;
     RECT  36.744 53.845 37.728 53.868 ;
     RECT  26.568 53.868 27.504 53.968 ;
     RECT  28.008 53.868 28.944 53.968 ;
     RECT  36.744 53.868 37.68 53.891 ;
     RECT  38.184 53.868 39.12 53.891 ;
     RECT  41.544 53.868 42.48 53.968 ;
  END
END ot_s81_engram_mixq_shctl
END LIBRARY
